VERSION 5.8 ;
BUSBITCHARS "[]" ;
DIVIDERCHAR "/" ;

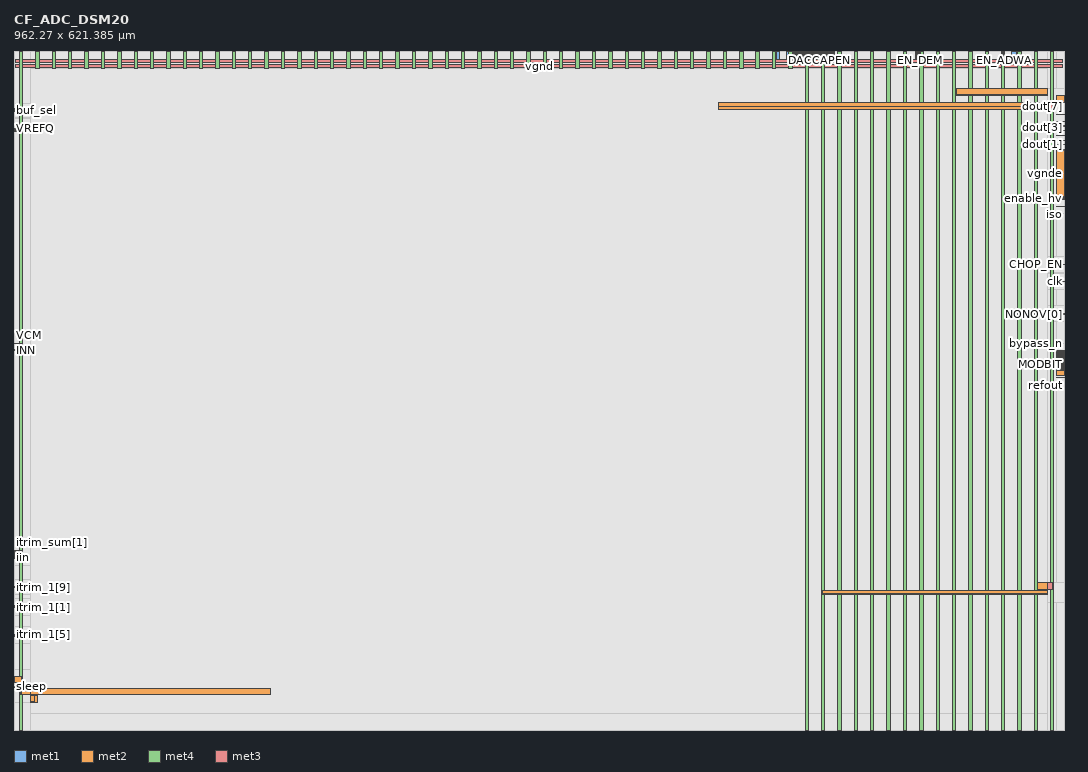
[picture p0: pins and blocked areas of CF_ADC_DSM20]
MACRO CF_ADC_DSM20
  CLASS BLOCK ;
  ORIGIN 0 0 ;
  FOREIGN CF_ADC_DSM20 0 0 ;
  SIZE 962.27 BY 621.385 ;
  PIN bw[0]
    DIRECTION INPUT ;
    USE SIGNAL ;
    PORT
      LAYER met1 ;
        RECT 713.61 614.485 713.81 621.385 ;
    END
  END bw[0]
  PIN bw[1]
    DIRECTION INPUT ;
    USE SIGNAL ;
    PORT
      LAYER met1 ;
        RECT 714.04 614.485 714.24 621.385 ;
    END
  END bw[1]
  PIN bw[2]
    DIRECTION INPUT ;
    USE SIGNAL ;
    PORT
      LAYER met1 ;
        RECT 714.47 614.485 714.67 621.385 ;
    END
  END bw[2]
  PIN SUMCAPIN[4]
    DIRECTION INPUT ;
    USE SIGNAL ;
    PORT
      LAYER met1 ;
        RECT 715.33 614.485 715.53 621.385 ;
    END
  END SUMCAPIN[4]
  PIN SUMCAPIN[3]
    DIRECTION INPUT ;
    USE SIGNAL ;
    PORT
      LAYER met1 ;
        RECT 715.76 614.485 715.96 621.385 ;
    END
  END SUMCAPIN[3]
  PIN SUMCAPIN[2]
    DIRECTION INPUT ;
    USE SIGNAL ;
    PORT
      LAYER met1 ;
        RECT 716.19 614.485 716.39 621.385 ;
    END
  END SUMCAPIN[2]
  PIN SUMCAPIN[1]
    DIRECTION INPUT ;
    USE SIGNAL ;
    PORT
      LAYER met1 ;
        RECT 716.62 614.485 716.82 621.385 ;
    END
  END SUMCAPIN[1]
  PIN SUMCAPIN[0]
    DIRECTION INPUT ;
    USE SIGNAL ;
    PORT
      LAYER met1 ;
        RECT 717.05 614.485 717.25 621.385 ;
    END
  END SUMCAPIN[0]
  PIN SUMCAPFB_EN
    DIRECTION INPUT ;
    USE SIGNAL ;
    PORT
      LAYER met1 ;
        RECT 717.48 614.485 717.68 621.385 ;
    END
  END SUMCAPFB_EN
  PIN SUMCAPFB[1]
    DIRECTION INPUT ;
    USE SIGNAL ;
    PORT
      LAYER met1 ;
        RECT 717.91 614.485 718.11 621.385 ;
    END
  END SUMCAPFB[1]
  PIN SUMCAPFB[2]
    DIRECTION INPUT ;
    USE SIGNAL ;
    PORT
      LAYER met1 ;
        RECT 718.34 614.485 718.54 621.385 ;
    END
  END SUMCAPFB[2]
  PIN SUMCAPFB[3]
    DIRECTION INPUT ;
    USE SIGNAL ;
    PORT
      LAYER met1 ;
        RECT 718.77 614.485 718.97 621.385 ;
    END
  END SUMCAPFB[3]
  PIN SUMCAPFB[0]
    DIRECTION INPUT ;
    USE SIGNAL ;
    PORT
      LAYER met1 ;
        RECT 719.2 614.485 719.4 621.385 ;
    END
  END SUMCAPFB[0]
  PIN refsel[15]
    DIRECTION INPUT ;
    USE SIGNAL ;
    PORT
      LAYER met1 ;
        RECT 719.63 614.485 719.83 621.385 ;
    END
  END refsel[15]
  PIN refsel[14]
    DIRECTION INPUT ;
    USE SIGNAL ;
    PORT
      LAYER met1 ;
        RECT 720.06 614.485 720.26 621.385 ;
    END
  END refsel[14]
  PIN refsel[13]
    DIRECTION INPUT ;
    USE SIGNAL ;
    PORT
      LAYER met1 ;
        RECT 720.49 614.485 720.69 621.385 ;
    END
  END refsel[13]
  PIN refsel[12]
    DIRECTION INPUT ;
    USE SIGNAL ;
    PORT
      LAYER met1 ;
        RECT 720.92 614.485 721.12 621.385 ;
    END
  END refsel[12]
  PIN refsel[11]
    DIRECTION INPUT ;
    USE SIGNAL ;
    PORT
      LAYER met1 ;
        RECT 721.35 614.485 721.55 621.385 ;
    END
  END refsel[11]
  PIN refsel[10]
    DIRECTION INPUT ;
    USE SIGNAL ;
    PORT
      LAYER met1 ;
        RECT 721.78 614.485 721.98 621.385 ;
    END
  END refsel[10]
  PIN refsel[9]
    DIRECTION INPUT ;
    USE SIGNAL ;
    PORT
      LAYER met1 ;
        RECT 722.21 614.485 722.41 621.385 ;
    END
  END refsel[9]
  PIN refsel[8]
    DIRECTION INPUT ;
    USE SIGNAL ;
    PORT
      LAYER met1 ;
        RECT 722.64 614.485 722.84 621.385 ;
    END
  END refsel[8]
  PIN refsel[7]
    DIRECTION INPUT ;
    USE SIGNAL ;
    PORT
      LAYER met1 ;
        RECT 723.07 614.485 723.27 621.385 ;
    END
  END refsel[7]
  PIN refsel[6]
    DIRECTION INPUT ;
    USE SIGNAL ;
    PORT
      LAYER met1 ;
        RECT 723.5 614.485 723.7 621.385 ;
    END
  END refsel[6]
  PIN refsel[5]
    DIRECTION INPUT ;
    USE SIGNAL ;
    PORT
      LAYER met1 ;
        RECT 723.93 614.485 724.13 621.385 ;
    END
  END refsel[5]
  PIN refsel[4]
    DIRECTION INPUT ;
    USE SIGNAL ;
    PORT
      LAYER met1 ;
        RECT 724.36 614.485 724.56 621.385 ;
    END
  END refsel[4]
  PIN refsel[3]
    DIRECTION INPUT ;
    USE SIGNAL ;
    PORT
      LAYER met1 ;
        RECT 724.79 614.485 724.99 621.385 ;
    END
  END refsel[3]
  PIN refsel[2]
    DIRECTION INPUT ;
    USE SIGNAL ;
    PORT
      LAYER met1 ;
        RECT 725.22 614.485 725.42 621.385 ;
    END
  END refsel[2]
  PIN refsel[1]
    DIRECTION INPUT ;
    USE SIGNAL ;
    PORT
      LAYER met1 ;
        RECT 725.65 614.485 725.85 621.385 ;
    END
  END refsel[1]
  PIN refsel[0]
    DIRECTION INPUT ;
    USE SIGNAL ;
    PORT
      LAYER met1 ;
        RECT 727.8 614.485 728 621.385 ;
    END
  END refsel[0]
  PIN SUMCAP3[0]
    DIRECTION INPUT ;
    USE SIGNAL ;
    PORT
      LAYER met1 ;
        RECT 726.08 614.485 726.28 621.385 ;
    END
  END SUMCAP3[0]
  PIN SUMCAP3[1]
    DIRECTION INPUT ;
    USE SIGNAL ;
    PORT
      LAYER met1 ;
        RECT 726.51 614.485 726.71 621.385 ;
    END
  END SUMCAP3[1]
  PIN SUMCAP3[2]
    DIRECTION INPUT ;
    USE SIGNAL ;
    PORT
      LAYER met1 ;
        RECT 726.94 614.485 727.14 621.385 ;
    END
  END SUMCAP3[2]
  PIN SUMCAP3_EN
    DIRECTION INPUT ;
    USE SIGNAL ;
    PORT
      LAYER met1 ;
        RECT 727.37 614.485 727.57 621.385 ;
    END
  END SUMCAP3_EN
  PIN SUMCAP2_EN
    DIRECTION INPUT ;
    USE SIGNAL ;
    PORT
      LAYER met1 ;
        RECT 728.23 614.485 728.43 621.385 ;
    END
  END SUMCAP2_EN
  PIN SUMCAP2[2]
    DIRECTION INPUT ;
    USE SIGNAL ;
    PORT
      LAYER met1 ;
        RECT 728.66 614.485 728.86 621.385 ;
    END
  END SUMCAP2[2]
  PIN SUMCAP2[1]
    DIRECTION INPUT ;
    USE SIGNAL ;
    PORT
      LAYER met1 ;
        RECT 729.09 614.485 729.29 621.385 ;
    END
  END SUMCAP2[1]
  PIN SUMCAP2[0]
    DIRECTION INPUT ;
    USE SIGNAL ;
    PORT
      LAYER met1 ;
        RECT 729.52 614.485 729.72 621.385 ;
    END
  END SUMCAP2[0]
  PIN SUMCAP1_EN
    DIRECTION INPUT ;
    USE SIGNAL ;
    PORT
      LAYER met1 ;
        RECT 729.95 614.485 730.15 621.385 ;
    END
  END SUMCAP1_EN
  PIN SUMCAP1[1]
    DIRECTION INPUT ;
    USE SIGNAL ;
    PORT
      LAYER met1 ;
        RECT 730.81 614.485 731.01 621.385 ;
    END
  END SUMCAP1[1]
  PIN SUMCAP1[0]
    DIRECTION INPUT ;
    USE SIGNAL ;
    PORT
      LAYER met1 ;
        RECT 731.24 614.485 731.44 621.385 ;
    END
  END SUMCAP1[0]
  PIN SUMCAP1[2]
    DIRECTION INPUT ;
    USE SIGNAL ;
    PORT
      LAYER met1 ;
        RECT 732.1 614.485 732.3 621.385 ;
    END
  END SUMCAP1[2]
  PIN IPCAP3[1]
    DIRECTION INPUT ;
    USE SIGNAL ;
    PORT
      LAYER met1 ;
        RECT 730.38 614.485 730.58 621.385 ;
    END
  END IPCAP3[1]
  PIN IPCAP3[2]
    DIRECTION INPUT ;
    USE SIGNAL ;
    PORT
      LAYER met1 ;
        RECT 731.67 614.485 731.87 621.385 ;
    END
  END IPCAP3[2]
  PIN IPCAP3[0]
    DIRECTION INPUT ;
    USE SIGNAL ;
    PORT
      LAYER met1 ;
        RECT 732.53 614.485 732.73 621.385 ;
    END
  END IPCAP3[0]
  PIN IPCAP2[2]
    DIRECTION INPUT ;
    USE SIGNAL ;
    PORT
      LAYER met1 ;
        RECT 732.96 614.485 733.16 621.385 ;
    END
  END IPCAP2[2]
  PIN IPCAP2[1]
    DIRECTION INPUT ;
    USE SIGNAL ;
    PORT
      LAYER met1 ;
        RECT 733.39 614.485 733.59 621.385 ;
    END
  END IPCAP2[1]
  PIN IPCAP2[0]
    DIRECTION INPUT ;
    USE SIGNAL ;
    PORT
      LAYER met1 ;
        RECT 733.82 614.485 734.02 621.385 ;
    END
  END IPCAP2[0]
  PIN FCAP3[3]
    DIRECTION INOUT ;
    USE SIGNAL ;
    PORT
      LAYER met1 ;
        RECT 734.25 614.485 734.45 621.385 ;
    END
  END FCAP3[3]
  PIN FCAP3[2]
    DIRECTION INOUT ;
    USE SIGNAL ;
    PORT
      LAYER met1 ;
        RECT 734.68 614.485 734.88 621.385 ;
    END
  END FCAP3[2]
  PIN FCAP3[0]
    DIRECTION INOUT ;
    USE SIGNAL ;
    PORT
      LAYER met1 ;
        RECT 735.54 614.485 735.74 621.385 ;
    END
  END FCAP3[0]
  PIN FCAP3[1]
    DIRECTION INOUT ;
    USE SIGNAL ;
    PORT
      LAYER met1 ;
        RECT 735.97 614.485 736.17 621.385 ;
    END
  END FCAP3[1]
  PIN FCAP2[3]
    DIRECTION INOUT ;
    USE SIGNAL ;
    PORT
      LAYER met1 ;
        RECT 735.11 614.485 735.31 621.385 ;
    END
  END FCAP2[3]
  PIN FCAP2[2]
    DIRECTION INOUT ;
    USE SIGNAL ;
    PORT
      LAYER met1 ;
        RECT 736.4 614.485 736.6 621.385 ;
    END
  END FCAP2[2]
  PIN FCAP2[1]
    DIRECTION INOUT ;
    USE SIGNAL ;
    PORT
      LAYER met1 ;
        RECT 736.83 614.485 737.03 621.385 ;
    END
  END FCAP2[1]
  PIN FCAP2[0]
    DIRECTION INOUT ;
    USE SIGNAL ;
    PORT
      LAYER met1 ;
        RECT 737.26 614.485 737.46 621.385 ;
    END
  END FCAP2[0]
  PIN DACCAPEN
    DIRECTION INPUT ;
    USE SIGNAL ;
    PORT
      LAYER met1 ;
        RECT 737.69 614.485 737.89 621.385 ;
    END
  END DACCAPEN
  PIN DACCAP[5]
    DIRECTION INPUT ;
    USE SIGNAL ;
    PORT
      LAYER met1 ;
        RECT 738.12 614.485 738.32 621.385 ;
    END
  END DACCAP[5]
  PIN DACCAP[4]
    DIRECTION INPUT ;
    USE SIGNAL ;
    PORT
      LAYER met1 ;
        RECT 738.55 614.485 738.75 621.385 ;
    END
  END DACCAP[4]
  PIN DACCAP[3]
    DIRECTION INPUT ;
    USE SIGNAL ;
    PORT
      LAYER met1 ;
        RECT 738.98 614.485 739.18 621.385 ;
    END
  END DACCAP[3]
  PIN DACCAP[0]
    DIRECTION INPUT ;
    USE SIGNAL ;
    PORT
      LAYER met1 ;
        RECT 739.41 614.485 739.61 621.385 ;
    END
  END DACCAP[0]
  PIN DACCAP[1]
    DIRECTION INPUT ;
    USE SIGNAL ;
    PORT
      LAYER met1 ;
        RECT 739.84 614.485 740.04 621.385 ;
    END
  END DACCAP[1]
  PIN DACCAP[2]
    DIRECTION INPUT ;
    USE SIGNAL ;
    PORT
      LAYER met1 ;
        RECT 740.27 614.485 740.47 621.385 ;
    END
  END DACCAP[2]
  PIN IPCAP1[6]
    DIRECTION INPUT ;
    USE SIGNAL ;
    PORT
      LAYER met1 ;
        RECT 740.7 614.485 740.9 621.385 ;
    END
  END IPCAP1[6]
  PIN IPCAP1[5]
    DIRECTION INPUT ;
    USE SIGNAL ;
    PORT
      LAYER met1 ;
        RECT 741.13 614.485 741.33 621.385 ;
    END
  END IPCAP1[5]
  PIN IPCAP1[4]
    DIRECTION INPUT ;
    USE SIGNAL ;
    PORT
      LAYER met1 ;
        RECT 741.56 614.485 741.76 621.385 ;
    END
  END IPCAP1[4]
  PIN IPCAP1[3]
    DIRECTION INPUT ;
    USE SIGNAL ;
    PORT
      LAYER met1 ;
        RECT 741.99 614.485 742.19 621.385 ;
    END
  END IPCAP1[3]
  PIN IPCAP1[2]
    DIRECTION INPUT ;
    USE SIGNAL ;
    PORT
      LAYER met1 ;
        RECT 742.42 614.485 742.62 621.385 ;
    END
  END IPCAP1[2]
  PIN IPCAP1[1]
    DIRECTION INPUT ;
    USE SIGNAL ;
    PORT
      LAYER met1 ;
        RECT 742.85 614.485 743.05 621.385 ;
    END
  END IPCAP1[1]
  PIN IPCAP1[0]
    DIRECTION INPUT ;
    USE SIGNAL ;
    PORT
      LAYER met1 ;
        RECT 745 614.485 745.2 621.385 ;
    END
  END IPCAP1[0]
  PIN FCAP1[3]
    DIRECTION INPUT ;
    USE SIGNAL ;
    PORT
      LAYER met1 ;
        RECT 743.28 614.485 743.48 621.385 ;
    END
  END FCAP1[3]
  PIN FCAP1[4]
    DIRECTION INPUT ;
    USE SIGNAL ;
    PORT
      LAYER met1 ;
        RECT 743.71 614.485 743.91 621.385 ;
    END
  END FCAP1[4]
  PIN FCAP1[5]
    DIRECTION INPUT ;
    USE SIGNAL ;
    PORT
      LAYER met1 ;
        RECT 744.14 614.485 744.34 621.385 ;
    END
  END FCAP1[5]
  PIN FCAP1[6]
    DIRECTION INPUT ;
    USE SIGNAL ;
    PORT
      LAYER met1 ;
        RECT 744.57 614.485 744.77 621.385 ;
    END
  END FCAP1[6]
  PIN FCAP1[2]
    DIRECTION INPUT ;
    USE SIGNAL ;
    PORT
      LAYER met1 ;
        RECT 745.43 614.485 745.63 621.385 ;
    END
  END FCAP1[2]
  PIN FCAP1[1]
    DIRECTION INPUT ;
    USE SIGNAL ;
    PORT
      LAYER met1 ;
        RECT 745.86 614.485 746.06 621.385 ;
    END
  END FCAP1[1]
  PIN FCAP1[0]
    DIRECTION INPUT ;
    USE SIGNAL ;
    PORT
      LAYER met1 ;
        RECT 746.29 614.485 746.49 621.385 ;
    END
  END FCAP1[0]
  PIN RESCAPEN
    DIRECTION INPUT ;
    USE SIGNAL ;
    PORT
      LAYER met1 ;
        RECT 746.72 614.485 746.92 621.385 ;
    END
  END RESCAPEN
  PIN FCHOP[1]
    DIRECTION INPUT ;
    USE SIGNAL ;
    PORT
      LAYER met2 ;
        RECT 955.37 339.81 962.27 340.01 ;
    END
  END FCHOP[1]
  PIN FCHOP[0]
    DIRECTION INPUT ;
    USE SIGNAL ;
    PORT
      LAYER met2 ;
        RECT 955.37 340.24 962.27 340.44 ;
    END
  END FCHOP[0]
  PIN ODET
    DIRECTION INPUT ;
    USE SIGNAL ;
    PORT
      LAYER met2 ;
        RECT 955.37 340.67 962.27 340.87 ;
    END
  END ODET
  PIN ODET_TH[4]
    DIRECTION INPUT ;
    USE SIGNAL ;
    PORT
      LAYER met2 ;
        RECT 955.37 341.1 962.27 341.3 ;
    END
  END ODET_TH[4]
  PIN ODET_TH[3]
    DIRECTION INPUT ;
    USE SIGNAL ;
    PORT
      LAYER met2 ;
        RECT 955.37 341.53 962.27 341.73 ;
    END
  END ODET_TH[3]
  PIN ODET_TH[2]
    DIRECTION INPUT ;
    USE SIGNAL ;
    PORT
      LAYER met2 ;
        RECT 955.37 341.96 962.27 342.16 ;
    END
  END ODET_TH[2]
  PIN ODET_TH[1]
    DIRECTION INPUT ;
    USE SIGNAL ;
    PORT
      LAYER met2 ;
        RECT 955.37 342.39 962.27 342.59 ;
    END
  END ODET_TH[1]
  PIN ODET_TH[0]
    DIRECTION INPUT ;
    USE SIGNAL ;
    PORT
      LAYER met2 ;
        RECT 955.37 342.82 962.27 343.02 ;
    END
  END ODET_TH[0]
  PIN RESET1
    DIRECTION INPUT ;
    USE SIGNAL ;
    PORT
      LAYER met2 ;
        RECT 955.37 343.25 962.27 343.45 ;
    END
  END RESET1
  PIN RESET2
    DIRECTION INPUT ;
    USE SIGNAL ;
    PORT
      LAYER met2 ;
        RECT 955.37 343.68 962.27 343.88 ;
    END
  END RESET2
  PIN RESET3
    DIRECTION INPUT ;
    USE SIGNAL ;
    PORT
      LAYER met2 ;
        RECT 955.37 344.11 962.27 344.31 ;
    END
  END RESET3
  PIN disable_mod
    DIRECTION INPUT ;
    USE SIGNAL ;
    PORT
      LAYER met2 ;
        RECT 955.37 344.54 962.27 344.74 ;
    END
  END disable_mod
  PIN dig_test_sel[2]
    DIRECTION INOUT ;
    USE SIGNAL ;
    PORT
      LAYER met2 ;
        RECT 955.37 344.97 962.27 345.17 ;
    END
  END dig_test_sel[2]
  PIN dig_test_sel[1]
    DIRECTION INOUT ;
    USE SIGNAL ;
    PORT
      LAYER met2 ;
        RECT 955.37 345.4 962.27 345.6 ;
    END
  END dig_test_sel[1]
  PIN dig_test_sel[0]
    DIRECTION INOUT ;
    USE SIGNAL ;
    PORT
      LAYER met2 ;
        RECT 955.37 345.94 962.27 346.08 ;
        RECT 955.37 345.83 962.27 345.99 ;
    END
  END dig_test_sel[0]
  PIN qlev[0]
    DIRECTION INPUT ;
    USE SIGNAL ;
    PORT
      LAYER met2 ;
        RECT 955.37 346.69 962.27 346.89 ;
    END
  END qlev[0]
  PIN qlev[1]
    DIRECTION INPUT ;
    USE SIGNAL ;
    PORT
      LAYER met2 ;
        RECT 955.37 346.26 962.27 346.46 ;
    END
  END qlev[1]
  PIN CHOP_EN
    DIRECTION INPUT ;
    USE SIGNAL ;
    PORT
      LAYER met2 ;
        RECT 955.37 426.54 962.27 426.86 ;
    END
  END CHOP_EN
  PIN clk
    DIRECTION INPUT ;
    USE SIGNAL ;
    PORT
      LAYER met2 ;
        RECT 955.37 410.95 962.27 411.21 ;
    END
  END clk
  PIN NONOV[1]
    DIRECTION INPUT ;
    USE SIGNAL ;
    PORT
      LAYER met2 ;
        RECT 955.37 381.45 962.27 381.71 ;
    END
  END NONOV[1]
  PIN NONOV[0]
    DIRECTION INPUT ;
    USE SIGNAL ;
    PORT
      LAYER met2 ;
        RECT 955.37 380.87 962.27 381.13 ;
    END
  END NONOV[0]
  PIN MODBIT
    DIRECTION INPUT ;
    USE SIGNAL ;
    PORT
      LAYER met2 ;
        RECT 955.37 334.785 962.27 334.925 ;
    END
  END MODBIT
  PIN SIGN
    DIRECTION INPUT ;
    USE SIGNAL ;
    PORT
      LAYER met2 ;
        RECT 955.37 334.355 962.27 334.555 ;
    END
  END SIGN
  PIN overload_det_one
    DIRECTION OUTPUT ;
    USE SIGNAL ;
    PORT
      LAYER met2 ;
        RECT 955.37 333.42 962.27 333.62 ;
    END
  END overload_det_one
  PIN overload_det_zero
    DIRECTION OUTPUT ;
    USE SIGNAL ;
    PORT
      LAYER met2 ;
        RECT 955.37 332.925 962.27 333.125 ;
    END
  END overload_det_zero
  PIN SCANOUTPUT
    DIRECTION OUTPUT ;
    USE SIGNAL ;
    PORT
      LAYER met2 ;
        RECT 955.37 332.465 962.27 332.665 ;
    END
  END SCANOUTPUT
  PIN buf_chopclk
    DIRECTION OUTPUT ;
    USE SIGNAL ;
    PORT
      LAYER met2 ;
        RECT 955.37 331.98 962.27 332.18 ;
    END
  END buf_chopclk
  PIN test_dig_out
    DIRECTION OUTPUT ;
    USE SIGNAL ;
    PORT
      LAYER met2 ;
        RECT 955.37 331.485 962.27 331.685 ;
    END
  END test_dig_out
  PIN SUMP_TEST
    DIRECTION OUTPUT ;
    USE SIGNAL ;
    PORT
      LAYER met2 ;
        RECT 955.37 330.95 962.27 331.15 ;
    END
  END SUMP_TEST
  PIN dout[7]
    DIRECTION INOUT ;
    USE SIGNAL ;
    PORT
      LAYER met2 ;
        RECT 955.37 563.62 962.27 563.82 ;
    END
  END dout[7]
  PIN bw[3]
    DIRECTION INPUT ;
    USE SIGNAL ;
    PORT
      LAYER met1 ;
        RECT 713.18 614.485 713.38 621.385 ;
    END
  END bw[3]
  PIN dout[6]
    DIRECTION INOUT ;
    USE SIGNAL ;
    PORT
      LAYER met2 ;
        RECT 955.37 557.5 962.27 557.7 ;
    END
  END dout[6]
  PIN dout[5]
    DIRECTION INOUT ;
    USE SIGNAL ;
    PORT
      LAYER met2 ;
        RECT 955.37 553.51 962.27 553.71 ;
    END
  END dout[5]
  PIN dout[4]
    DIRECTION INOUT ;
    USE SIGNAL ;
    PORT
      LAYER met2 ;
        RECT 955.37 549.26 962.27 549.46 ;
    END
  END dout[4]
  PIN dout[3]
    DIRECTION INOUT ;
    USE SIGNAL ;
    PORT
      LAYER met2 ;
        RECT 955.37 544.81 962.27 545.01 ;
    END
  END dout[3]
  PIN dout[2]
    DIRECTION INOUT ;
    USE SIGNAL ;
    PORT
      LAYER met2 ;
        RECT 955.37 540.425 962.27 540.625 ;
    END
  END dout[2]
  PIN dout[1]
    DIRECTION INOUT ;
    USE SIGNAL ;
    PORT
      LAYER met2 ;
        RECT 955.37 536.19 962.27 536.39 ;
    END
  END dout[1]
  PIN dout[0]
    DIRECTION INOUT ;
    USE SIGNAL ;
    PORT
      LAYER met2 ;
        RECT 955.37 531.89 962.27 532.09 ;
    END
  END dout[0]
  PIN refout
    DIRECTION OUTPUT ;
    USE SIGNAL ;
    PORT
      LAYER met2 ;
        RECT 955.37 323.2 962.27 323.4 ;
    END
  END refout
  PIN vpwr
    DIRECTION INPUT ;
    USE POWER ;
    PORT
      LAYER met2 ;
        RECT 14.99 32.43 234.73 38.4 ;
        RECT 6.31 32.43 234.73 38.4 ;
        RECT 863.905 582.355 947.27 588.115 ;
        RECT 863.905 581.575 947.27 588.115 ;
        RECT 741.135 124.835 947.28 127.835 ;
        RECT 741.135 124.055 947.28 127.835 ;
      LAYER met4 ;
        RECT 5 0 8.1 621.385 ;
        RECT 35 606.53 38.1 621.385 ;
        RECT 65 606.53 68.1 621.385 ;
        RECT 95 606.53 98.1 621.385 ;
        RECT 125 606.53 128.1 621.385 ;
        RECT 155 606.53 158.1 621.385 ;
        RECT 185 606.53 188.1 621.385 ;
        RECT 215 606.53 218.1 621.385 ;
        RECT 245 606.53 248.1 621.385 ;
        RECT 275 606.53 278.1 621.385 ;
        RECT 305 606.53 308.1 621.385 ;
        RECT 335 606.53 338.1 621.385 ;
        RECT 365 606.53 368.1 621.385 ;
        RECT 395 606.53 398.1 621.385 ;
        RECT 425 606.53 428.1 621.385 ;
        RECT 455 606.53 458.1 621.385 ;
        RECT 485 606.53 488.1 621.385 ;
        RECT 515 606.53 518.1 621.385 ;
        RECT 545 606.53 548.1 621.385 ;
        RECT 575 606.53 578.1 621.385 ;
        RECT 605 606.53 608.1 621.385 ;
        RECT 635 606.53 638.1 621.385 ;
        RECT 665 606.53 668.1 621.385 ;
        RECT 695 606.53 698.1 621.385 ;
        RECT 725 0 728.1 621.385 ;
        RECT 755 0 758.1 621.385 ;
        RECT 785 0 788.1 621.385 ;
        RECT 815 0 818.1 621.385 ;
        RECT 845 0 848.1 621.385 ;
        RECT 875 0 878.1 621.385 ;
        RECT 905 0 908.1 621.385 ;
        RECT 935 0 938.1 621.385 ;
      LAYER met3 ;
        RECT 6.31 32.43 6.79 38.4 ;
        RECT 863.905 581.575 947.27 582.055 ;
        RECT 741.135 124.055 947.28 124.535 ;
        RECT 1.23 611.685 961.04 614.785 ;
    END
  END vpwr
  PIN vgnd
    DIRECTION INPUT ;
    USE GROUND ;
    PORT
      LAYER met2 ;
        RECT 15 26.485 19 31.39 ;
        RECT 15 25.42 19 26.485 ;
        RECT 15 25.42 21.79 31.39 ;
        RECT 942.27 571.53 947.285 574.675 ;
        RECT 645.36 568.675 947.285 571.53 ;
        RECT 645.36 568.675 947.285 574.675 ;
        RECT 938.365 128.99 947.27 134.995 ;
        RECT 938.365 128.99 947.27 134.995 ;
      LAYER met4 ;
        RECT 20 606.53 23.1 621.385 ;
        RECT 50 606.53 53.1 621.385 ;
        RECT 80 606.53 83.1 621.385 ;
        RECT 110 606.53 113.1 621.385 ;
        RECT 140 606.53 143.1 621.385 ;
        RECT 170 606.53 173.1 621.385 ;
        RECT 200 606.53 203.1 621.385 ;
        RECT 230 606.53 233.1 621.385 ;
        RECT 260 606.53 263.1 621.385 ;
        RECT 290 606.53 293.1 621.385 ;
        RECT 320 606.53 323.1 621.385 ;
        RECT 350 606.53 353.1 621.385 ;
        RECT 380 606.53 383.1 621.385 ;
        RECT 410 606.53 413.1 621.385 ;
        RECT 440 606.53 443.1 621.385 ;
        RECT 470 606.53 473.1 621.385 ;
        RECT 500 606.53 503.1 621.385 ;
        RECT 530 606.53 533.1 621.385 ;
        RECT 560 606.53 563.1 621.385 ;
        RECT 590 606.53 593.1 621.385 ;
        RECT 620 606.53 623.1 621.385 ;
        RECT 650 606.53 653.1 621.385 ;
        RECT 680 606.53 683.1 621.385 ;
        RECT 710 606.53 713.1 621.385 ;
        RECT 740 0 743.1 621.385 ;
        RECT 770 0 773.1 621.385 ;
        RECT 800 0 803.1 621.385 ;
        RECT 830 0 833.1 621.385 ;
        RECT 860 0 863.1 621.385 ;
        RECT 890 0 893.1 621.385 ;
        RECT 920 0 923.1 621.385 ;
        RECT 950 0 953.1 621.385 ;
      LAYER met3 ;
        RECT 21.31 25.42 21.79 31.39 ;
        RECT 645.36 568.675 951.79 574.675 ;
        RECT 938.365 128.99 951.79 134.995 ;
        RECT 1.23 606.885 961.04 609.985 ;
    END
  END vgnd
  PIN RESCAP[2]
    DIRECTION INPUT ;
    USE SIGNAL ;
    PORT
      LAYER met1 ;
        RECT 747.15 614.485 747.35 621.385 ;
    END
  END RESCAP[2]
  PIN RESCAP[0]
    DIRECTION INPUT ;
    USE SIGNAL ;
    PORT
      LAYER met1 ;
        RECT 748.01 614.485 748.21 621.385 ;
    END
  END RESCAP[0]
  PIN RESCAP[1]
    DIRECTION INPUT ;
    USE SIGNAL ;
    PORT
      LAYER met1 ;
        RECT 749.3 614.485 749.5 621.385 ;
    END
  END RESCAP[1]
  PIN IPCAP1OFFSET
    DIRECTION INPUT ;
    USE SIGNAL ;
    PORT
      LAYER met1 ;
        RECT 747.58 614.485 747.78 621.385 ;
    END
  END IPCAP1OFFSET
  PIN IPCAP3EN
    DIRECTION INPUT ;
    USE SIGNAL ;
    PORT
      LAYER met1 ;
        RECT 748.44 614.485 748.64 621.385 ;
    END
  END IPCAP3EN
  PIN IPCAP2EN
    DIRECTION INPUT ;
    USE SIGNAL ;
    PORT
      LAYER met1 ;
        RECT 748.87 614.485 749.07 621.385 ;
    END
  END IPCAP2EN
  PIN IPCAP1EN
    DIRECTION INPUT ;
    USE SIGNAL ;
    PORT
      LAYER met1 ;
        RECT 749.73 614.485 749.93 621.385 ;
    END
  END IPCAP1EN
  PIN FCAP3EN
    DIRECTION INPUT ;
    USE SIGNAL ;
    PORT
      LAYER met1 ;
        RECT 750.16 614.485 750.36 621.385 ;
    END
  END FCAP3EN
  PIN FCAP2EN
    DIRECTION INPUT ;
    USE SIGNAL ;
    PORT
      LAYER met1 ;
        RECT 750.59 614.485 750.79 621.385 ;
    END
  END FCAP2EN
  PIN FCAP1EN
    DIRECTION INPUT ;
    USE SIGNAL ;
    PORT
      LAYER met1 ;
        RECT 751.45 614.485 751.65 621.385 ;
    END
  END FCAP1EN
  PIN FCAP1OFFSET
    DIRECTION INPUT ;
    USE SIGNAL ;
    PORT
      LAYER met1 ;
        RECT 751.02 614.485 751.22 621.385 ;
    END
  END FCAP1OFFSET
  PIN SUMCAPIN_EN
    DIRECTION INPUT ;
    USE SIGNAL ;
    PORT
      LAYER met1 ;
        RECT 714.9 614.485 715.1 621.385 ;
    END
  END SUMCAPIN_EN
  PIN INP
    DIRECTION INPUT ;
    USE SIGNAL ;
    PORT
      LAYER met1 ;
        RECT 0 348.745 6.9 349.045 ;
    END
  END INP
  PIN INN
    DIRECTION INPUT ;
    USE SIGNAL ;
    PORT
      LAYER met1 ;
        RECT 0 347.785 6.9 348.085 ;
    END
  END INN
  PIN EN_DEM
    DIRECTION INPUT ;
    USE SIGNAL ;
    PORT
      LAYER met1 ;
        RECT 830.565 614.485 830.765 621.385 ;
    END
  END EN_DEM
  PIN test[7]
    DIRECTION INOUT ;
    USE SIGNAL ;
    PORT
      LAYER met1 ;
        RECT 830.085 614.485 830.285 621.385 ;
    END
  END test[7]
  PIN test[6]
    DIRECTION INOUT ;
    USE SIGNAL ;
    PORT
      LAYER met1 ;
        RECT 829.605 614.485 829.805 621.385 ;
    END
  END test[6]
  PIN test[5]
    DIRECTION INOUT ;
    USE SIGNAL ;
    PORT
      LAYER met1 ;
        RECT 829.125 614.485 829.325 621.385 ;
    END
  END test[5]
  PIN test[4]
    DIRECTION INOUT ;
    USE SIGNAL ;
    PORT
      LAYER met1 ;
        RECT 828.645 614.485 828.845 621.385 ;
    END
  END test[4]
  PIN test[3]
    DIRECTION INOUT ;
    USE SIGNAL ;
    PORT
      LAYER met1 ;
        RECT 828.165 614.485 828.365 621.385 ;
    END
  END test[3]
  PIN test[2]
    DIRECTION INOUT ;
    USE SIGNAL ;
    PORT
      LAYER met1 ;
        RECT 827.685 614.485 827.885 621.385 ;
    END
  END test[2]
  PIN test[1]
    DIRECTION INOUT ;
    USE SIGNAL ;
    PORT
      LAYER met1 ;
        RECT 827.205 614.485 827.405 621.385 ;
    END
  END test[1]
  PIN test[0]
    DIRECTION INOUT ;
    USE SIGNAL ;
    PORT
      LAYER met1 ;
        RECT 826.725 614.485 826.925 621.385 ;
    END
  END test[0]
  PIN TESTMODE
    DIRECTION INPUT ;
    USE SIGNAL ;
    PORT
      LAYER met1 ;
        RECT 826.245 614.485 826.445 621.385 ;
    END
  END TESTMODE
  PIN EN_DWA
    DIRECTION INPUT ;
    USE SIGNAL ;
    PORT
      LAYER met1 ;
        RECT 906.96 614.485 907.16 621.385 ;
    END
  END EN_DWA
  PIN SCANINPUT
    DIRECTION INPUT ;
    USE SIGNAL ;
    PORT
      LAYER met1 ;
        RECT 906 614.485 906.2 621.385 ;
    END
  END SCANINPUT
  PIN SCANMODE
    DIRECTION INPUT ;
    USE SIGNAL ;
    PORT
      LAYER met1 ;
        RECT 905.04 614.485 905.24 621.385 ;
    END
  END SCANMODE
  PIN SCANCLK
    DIRECTION INPUT ;
    USE SIGNAL ;
    PORT
      LAYER met1 ;
        RECT 905.52 614.485 905.72 621.385 ;
    END
  END SCANCLK
  PIN SCANEN
    DIRECTION INPUT ;
    USE SIGNAL ;
    PORT
      LAYER met1 ;
        RECT 906.48 614.485 906.68 621.385 ;
    END
  END SCANEN
  PIN reset_b
    DIRECTION INPUT ;
    USE SIGNAL ;
    PORT
      LAYER met1 ;
        RECT 904.56 614.485 904.76 621.385 ;
    END
  END reset_b
  PIN VCM
    DIRECTION INPUT ;
    USE SIGNAL ;
    PORT
      LAYER met1 ;
        RECT 0 354.06 6.9 354.36 ;
    END
  END VCM
  PIN vgndd_vnb
    DIRECTION INOUT ;
    USE SIGNAL ;
    PORT
      LAYER met1 ;
        RECT 913.8 614.485 918.775 621.385 ;
    END
  END vgndd_vnb
  PIN VGND_DAC
    DIRECTION INPUT ;
    USE SIGNAL ;
    PORT
      LAYER met1 ;
        RECT 0 548.45 6.9 549.225 ;
    END
  END VGND_DAC
  PIN VREFQ
    DIRECTION INPUT ;
    USE SIGNAL ;
    PORT
      LAYER met1 ;
        RECT 0 550.8 6.9 551.04 ;
    END
  END VREFQ
  PIN EN_ADWA
    DIRECTION INPUT ;
    USE SIGNAL ;
    PORT
      LAYER met1 ;
        RECT 907.48 614.485 907.68 621.385 ;
    END
  END EN_ADWA
  PIN PBUF_INP
    DIRECTION INPUT ;
    USE SIGNAL ;
    PORT
      LAYER met1 ;
        RECT 0 568.455 6.9 568.705 ;
    END
  END PBUF_INP
  PIN VREF
    DIRECTION INPUT ;
    USE SIGNAL ;
    PORT
      LAYER met1 ;
        RECT 0 549.88 6.9 550.185 ;
    END
  END VREF
  PIN PBUF_INN
    DIRECTION INPUT ;
    USE SIGNAL ;
    PORT
      LAYER met1 ;
        RECT 0 569.215 6.9 569.465 ;
    END
  END PBUF_INN
  PIN vgnde_vnb
    DIRECTION INPUT ;
    USE SIGNAL ;
    PORT
      LAYER met2 ;
        RECT 955.37 487.325 962.27 487.72 ;
    END
  END vgnde_vnb
  PIN vgnde
    DIRECTION INPUT ;
    USE SIGNAL ;
    PORT
      LAYER met2 ;
        RECT 955.37 488.97 962.27 531.195 ;
        RECT 955.37 487.965 962.27 488.97 ;
    END
  END vgnde
  PIN vpwr_ext
    DIRECTION INPUT ;
    USE SIGNAL ;
    PORT
      LAYER met1 ;
        RECT 698.665 614.485 701.655 621.385 ;
    END
  END vpwr_ext
  PIN vpwr_cp
    DIRECTION INPUT ;
    USE SIGNAL ;
    PORT
      LAYER met2 ;
        RECT 955.37 324.72 962.27 329.135 ;
    END
  END vpwr_cp
  PIN vpwr_cp_dc
    DIRECTION INOUT ;
    USE SIGNAL ;
    PORT
      LAYER met1 ;
        RECT 707.82 614.485 709.49 621.385 ;
    END
  END vpwr_cp_dc
  PIN SUMN_TEST
    DIRECTION OUTPUT ;
    USE SIGNAL ;
    PORT
      LAYER met2 ;
        RECT 955.37 330.455 962.27 330.655 ;
    END
  END SUMN_TEST
  PIN bypass_n
    DIRECTION INPUT ;
    USE SIGNAL ;
    PORT
      LAYER met2 ;
        RECT 955.37 347.12 962.27 347.26 ;
    END
  END bypass_n
  PIN bypass_p
    DIRECTION INPUT ;
    USE SIGNAL ;
    PORT
      LAYER met2 ;
        RECT 955.37 347.49 962.27 347.63 ;
    END
  END bypass_p
  PIN phi2_buffer
    DIRECTION INOUT ;
    USE SIGNAL ;
    PORT
      LAYER met2 ;
        RECT 955.37 335.2 962.27 335.34 ;
    END
  END phi2_buffer
  PIN iso
    DIRECTION INOUT ;
    USE SIGNAL ;
    PORT
      LAYER met2 ;
        RECT 955.37 479.9 962.27 480.04 ;
    END
  END iso
  PIN enable_hv
    DIRECTION INOUT ;
    USE SIGNAL ;
    PORT
      LAYER met2 ;
        RECT 955.37 486.565 962.27 486.705 ;
    END
  END enable_hv
  PIN MODINPUT
    DIRECTION INPUT ;
    USE SIGNAL ;
    PORT
      LAYER met2 ;
        RECT 955.37 333.89 962.27 334.09 ;
    END
  END MODINPUT
  PIN sleep
    DIRECTION INOUT ;
    USE SIGNAL ;
    PORT
      LAYER met2 ;
        RECT 0 39.295 6.9 39.535 ;
    END
  END sleep
  PIN buf_sel
    DIRECTION INPUT ;
    USE SIGNAL ;
    PORT
      LAYER met2 ;
        RECT 0 567.235 6.9 567.475 ;
    END
  END buf_sel
  PIN vpwrd_int
    DIRECTION INOUT ;
    USE SIGNAL ;
    PORT
      LAYER met2 ;
        RECT 955.37 575.185 962.27 581.185 ;
    END
  END vpwrd_int
  PIN vpwr_int
    DIRECTION INOUT ;
    USE SIGNAL ;
    PORT
      LAYER met2 ;
        RECT 0 43.95 6.9 48.75 ;
    END
  END vpwr_int
  PIN iinc
    DIRECTION INPUT ;
    USE SIGNAL ;
    PORT
      LAYER met2 ;
        RECT 0 158.35 6.9 158.65 ;
    END
  END iinc
  PIN itrim_1[9]
    DIRECTION INPUT ;
    USE SIGNAL ;
    PORT
      LAYER met2 ;
        RECT 0 130.785 6.9 131.095 ;
    END
  END itrim_1[9]
  PIN itrim_1[1]
    DIRECTION INPUT ;
    USE SIGNAL ;
    PORT
      LAYER met2 ;
        RECT 0 112.165 6.9 112.525 ;
    END
  END itrim_1[1]
  PIN itrim_1[2]
    DIRECTION INPUT ;
    USE SIGNAL ;
    PORT
      LAYER met2 ;
        RECT 0 112.675 6.9 113.035 ;
    END
  END itrim_1[2]
  PIN itrim_1[3]
    DIRECTION INPUT ;
    USE SIGNAL ;
    PORT
      LAYER met2 ;
        RECT 0 113.185 6.9 113.545 ;
    END
  END itrim_1[3]
  PIN itrim_1[4]
    DIRECTION INPUT ;
    USE SIGNAL ;
    PORT
      LAYER met2 ;
        RECT 0 113.695 6.9 114.055 ;
    END
  END itrim_1[4]
  PIN itrim_1[8]
    DIRECTION INPUT ;
    USE SIGNAL ;
    PORT
      LAYER met2 ;
        RECT 0 85.83 6.9 86.19 ;
    END
  END itrim_1[8]
  PIN itrim_1[7]
    DIRECTION INPUT ;
    USE SIGNAL ;
    PORT
      LAYER met2 ;
        RECT 0 86.34 6.9 86.7 ;
    END
  END itrim_1[7]
  PIN itrim_1[6]
    DIRECTION INPUT ;
    USE SIGNAL ;
    PORT
      LAYER met2 ;
        RECT 0 86.85 6.9 87.21 ;
    END
  END itrim_1[6]
  PIN itrim_1[5]
    DIRECTION INPUT ;
    USE SIGNAL ;
    PORT
      LAYER met2 ;
        RECT 0 87.36 6.9 87.72 ;
    END
  END itrim_1[5]
  PIN iin
    DIRECTION INPUT ;
    USE SIGNAL ;
    PORT
      LAYER met2 ;
        RECT 0 157.87 6.9 158.17 ;
    END
  END iin
  PIN itrim_sum[0]
    DIRECTION INPUT ;
    USE SIGNAL ;
    PORT
      LAYER met2 ;
        RECT 0 164.595 6.9 164.895 ;
    END
  END itrim_sum[0]
  PIN itrim_sum[1]
    DIRECTION INPUT ;
    USE SIGNAL ;
    PORT
      LAYER met2 ;
        RECT 0 164.115 6.9 164.415 ;
    END
  END itrim_sum[1]
  PIN itrim_sum[2]
    DIRECTION INPUT ;
    USE SIGNAL ;
    PORT
      LAYER met2 ;
        RECT 0 163.635 6.9 163.935 ;
    END
  END itrim_sum[2]
  PIN itrim_sum[3]
    DIRECTION INPUT ;
    USE SIGNAL ;
    PORT
      LAYER met2 ;
        RECT 0 163.155 6.9 163.455 ;
    END
  END itrim_sum[3]
  PIN itrim_sum[4]
    DIRECTION INPUT ;
    USE SIGNAL ;
    PORT
      LAYER met2 ;
        RECT 0 162.675 6.9 162.975 ;
    END
  END itrim_sum[4]
  PIN itrim_2_3[0]
    DIRECTION INPUT ;
    USE SIGNAL ;
    PORT
      LAYER met2 ;
        RECT 0 161.715 6.9 162.015 ;
    END
  END itrim_2_3[0]
  PIN itrim_2_3[1]
    DIRECTION INPUT ;
    USE SIGNAL ;
    PORT
      LAYER met2 ;
        RECT 0 161.235 6.9 161.535 ;
    END
  END itrim_2_3[1]
  PIN itrim_2_3[2]
    DIRECTION INPUT ;
    USE SIGNAL ;
    PORT
      LAYER met2 ;
        RECT 0 160.755 6.9 161.055 ;
    END
  END itrim_2_3[2]
  PIN itrim_2_3[3]
    DIRECTION INPUT ;
    USE SIGNAL ;
    PORT
      LAYER met2 ;
        RECT 0 160.275 6.9 160.575 ;
    END
  END itrim_2_3[3]
  PIN itrim_2_3[4]
    DIRECTION INPUT ;
    USE SIGNAL ;
    PORT
      LAYER met2 ;
        RECT 0 159.795 6.9 160.095 ;
    END
  END itrim_2_3[4]
  PIN itrim_sum[5]
    DIRECTION INPUT ;
    USE SIGNAL ;
    PORT
      LAYER met2 ;
        RECT 0 162.195 6.9 162.495 ;
    END
  END itrim_sum[5]
  PIN itrim_2_3[5]
    DIRECTION INPUT ;
    USE SIGNAL ;
    PORT
      LAYER met2 ;
        RECT 0 159.315 6.9 159.615 ;
    END
  END itrim_2_3[5]
  PIN itrim_1[0]
    DIRECTION INPUT ;
    USE SIGNAL ;
    PORT
      LAYER met2 ;
        RECT 0 157.39 6.9 157.69 ;
    END
  END itrim_1[0]
  PIN itrim_comp[3]
    DIRECTION INPUT ;
    USE SIGNAL ;
    PORT
      LAYER met2 ;
        RECT 955.37 335.57 962.27 335.71 ;
    END
  END itrim_comp[3]
  PIN itrim_comp[2]
    DIRECTION INPUT ;
    USE SIGNAL ;
    PORT
      LAYER met2 ;
        RECT 955.37 335.94 962.27 336.14 ;
    END
  END itrim_comp[2]
  PIN itrim_comp[1]
    DIRECTION INPUT ;
    USE SIGNAL ;
    PORT
      LAYER met2 ;
        RECT 955.37 336.37 962.27 336.57 ;
    END
  END itrim_comp[1]
  PIN itrim_comp[0]
    DIRECTION INPUT ;
    USE SIGNAL ;
    PORT
      LAYER met2 ;
        RECT 955.37 336.8 962.27 337 ;
    END
  END itrim_comp[0]
  PIN BUF_CHOP_EN
    DIRECTION INPUT ;
    USE SIGNAL ;
    PORT
      LAYER met2 ;
        RECT 955.37 337.23 962.27 337.43 ;
    END
  END BUF_CHOP_EN
  PIN BUF_FCHOP[2]
    DIRECTION INPUT ;
    USE SIGNAL ;
    PORT
      LAYER met2 ;
        RECT 955.37 337.66 962.27 337.86 ;
    END
  END BUF_FCHOP[2]
  PIN BUF_FCHOP[1]
    DIRECTION INPUT ;
    USE SIGNAL ;
    PORT
      LAYER met2 ;
        RECT 955.37 338.09 962.27 338.29 ;
    END
  END BUF_FCHOP[1]
  PIN BUF_FCHOP[0]
    DIRECTION INPUT ;
    USE SIGNAL ;
    PORT
      LAYER met2 ;
        RECT 955.37 338.52 962.27 338.72 ;
    END
  END BUF_FCHOP[0]
  PIN RESET_DEC_INPUT
    DIRECTION INPUT ;
    USE SIGNAL ;
    PORT
      LAYER met2 ;
        RECT 955.37 338.95 962.27 339.15 ;
    END
  END RESET_DEC_INPUT
  PIN FCHOP[2]
    DIRECTION INPUT ;
    USE SIGNAL ;
    PORT
      LAYER met2 ;
        RECT 955.37 339.38 962.27 339.58 ;
    END
  END FCHOP[2]
  OBS
    LAYER li1 ;
      RECT 739.84 530.05 740.04 559.94 ;
      RECT 742.42 530.05 742.62 559.94 ;
      RECT 738.98 530.05 739.18 559.94 ;
      RECT 743.71 528.355 743.91 558.945 ;
      RECT 745 530.05 745.2 559.94 ;
      RECT 746.72 530.05 746.92 559.94 ;
      RECT 751.02 530.05 751.22 559.94 ;
      RECT 748.87 528.355 749.07 558.945 ;
      RECT 747.15 528.355 747.35 558.945 ;
      RECT 750.59 528.355 750.79 558.945 ;
      RECT 748.01 528.355 748.21 558.945 ;
      RECT 746.29 528.355 746.49 558.945 ;
      RECT 745.43 528.355 745.63 558.945 ;
      RECT 749.73 528.355 749.93 558.945 ;
      RECT 747.58 530.05 747.78 559.94 ;
      RECT 748.44 530.05 748.64 559.94 ;
      RECT 745.86 530.05 746.06 559.94 ;
      RECT 750.16 530.05 750.36 559.94 ;
      RECT 749.3 530.05 749.5 559.94 ;
      RECT 753.625 530.05 753.825 561.29 ;
      RECT 752.765 530.05 752.965 559.94 ;
      RECT 754.915 528.355 755.115 561.29 ;
      RECT 754.485 530.05 754.685 561.29 ;
      RECT 755.345 530.05 755.545 561.29 ;
      RECT 754.055 528.355 754.255 561.29 ;
      RECT 753.195 528.355 753.395 561.29 ;
      RECT 751.45 528.355 751.65 558.945 ;
      RECT 755.775 528.355 755.975 561.29 ;
      RECT 752.335 528.355 752.535 558.945 ;
      RECT 756.635 528.355 756.835 561.29 ;
      RECT 751.905 530.05 752.105 559.94 ;
      RECT 756.205 530.05 756.405 561.29 ;
      RECT 906.185 538.79 907.085 538.96 ;
      RECT 906.915 537.38 907.085 538.79 ;
      RECT 906.685 535.43 906.855 536.51 ;
      RECT 913.23 501.24 913.46 551.67 ;
      RECT 863.675 575.33 895.195 575.62 ;
      RECT 863.53 582.835 895.065 584.835 ;
      RECT 941.92 526.615 943.27 591.885 ;
      RECT 531.5 527.74 532.79 573.39 ;
      RECT 532.475 518.405 532.705 527.74 ;
      RECT 502.615 591.39 503.145 591.685 ;
      RECT 534.665 583.625 543.285 584.145 ;
      RECT 520.3 591.525 520.96 591.695 ;
      RECT 521.965 591.525 522.5 591.695 ;
      RECT 563.74 591.525 564.4 591.695 ;
      RECT 562.2 591.525 562.72 591.695 ;
      RECT 580.66 591.525 581.32 591.695 ;
      RECT 582.325 591.525 582.86 591.695 ;
      RECT 535.555 588.07 536.225 588.435 ;
      RECT 503.375 591.525 504.075 591.695 ;
      RECT 639.345 545.715 649.735 545.885 ;
      RECT 639.345 545.885 639.515 559.945 ;
      RECT 639.345 531.075 649.735 531.805 ;
      RECT 639.345 531.805 639.515 545.715 ;
      RECT 649.565 558.005 649.8 559.945 ;
      RECT 649.565 519.03 649.735 531.075 ;
      RECT 649.565 517.015 649.8 519.03 ;
      RECT 649.565 545.885 649.735 558.005 ;
      RECT 649.565 531.805 649.735 545.715 ;
      RECT 639.345 517.015 639.515 531.075 ;
      RECT 639.345 559.945 649.8 560.475 ;
      RECT 639.345 516.7 649.8 517.015 ;
      RECT 633.75 515.34 654.875 516.405 ;
      RECT 638.96 548.245 639.13 560.82 ;
      RECT 650 516.405 650.255 560.82 ;
      RECT 638.96 560.825 650.17 560.99 ;
      RECT 638.96 560.82 650.255 560.825 ;
      RECT 638.96 516.405 639.13 528.625 ;
      RECT 617.03 591.525 617.69 591.695 ;
      RECT 615.49 591.525 616.025 591.695 ;
      RECT 633.95 591.525 634.61 591.695 ;
      RECT 635.615 591.525 636.15 591.695 ;
      RECT 667.565 591.525 668.225 591.695 ;
      RECT 665.885 591.525 666.58 591.695 ;
      RECT 656.36 505.08 710.11 506.05 ;
      RECT 656.36 517.62 710.11 518.7 ;
      RECT 654.43 498.96 710.935 499.64 ;
      RECT 654.43 511.505 710.935 512.185 ;
      RECT 682.79 524.755 682.99 550.055 ;
      RECT 682.355 524.755 682.555 550.055 ;
      RECT 684.095 524.755 684.295 550.055 ;
      RECT 688.445 524.755 688.645 550.055 ;
      RECT 686.27 524.755 686.47 550.055 ;
      RECT 686.705 524.755 686.905 550.055 ;
      RECT 688.01 524.755 688.21 550.055 ;
      RECT 687.14 524.755 687.34 550.055 ;
      RECT 688.88 524.755 689.08 550.055 ;
      RECT 685.835 524.755 686.035 550.055 ;
      RECT 687.575 524.755 687.775 550.055 ;
      RECT 684.965 524.755 685.165 550.055 ;
      RECT 685.4 524.755 685.6 550.055 ;
      RECT 683.66 524.755 683.86 550.055 ;
      RECT 684.53 524.755 684.73 550.055 ;
      RECT 683.225 524.755 683.425 550.055 ;
      RECT 684.485 591.525 685.145 591.695 ;
      RECT 713.18 530.05 713.38 559.94 ;
      RECT 713.61 528.355 713.81 558.945 ;
      RECT 717.05 528.355 717.25 558.945 ;
      RECT 714.47 528.355 714.67 558.945 ;
      RECT 718.34 530.05 718.54 559.94 ;
      RECT 715.33 528.355 715.53 558.945 ;
      RECT 718.77 528.355 718.97 558.945 ;
      RECT 716.19 528.355 716.39 558.945 ;
      RECT 717.91 528.355 718.11 558.945 ;
      RECT 719.63 528.355 719.83 557.625 ;
      RECT 720.06 530.05 720.26 559.94 ;
      RECT 714.9 530.05 715.1 559.94 ;
      RECT 716.62 530.05 716.82 559.94 ;
      RECT 719.2 530.05 719.4 559.94 ;
      RECT 715.76 530.05 715.96 559.94 ;
      RECT 714.04 530.05 714.24 559.94 ;
      RECT 717.48 530.05 717.68 559.94 ;
      RECT 720.49 528.355 720.69 558.945 ;
      RECT 722.64 530.05 722.84 559.94 ;
      RECT 725.22 530.05 725.42 559.94 ;
      RECT 723.5 530.05 723.7 559.94 ;
      RECT 726.08 530.05 726.28 559.94 ;
      RECT 724.36 530.05 724.56 559.94 ;
      RECT 724.79 528.355 724.99 558.945 ;
      RECT 721.78 530.05 721.98 559.94 ;
      RECT 723.07 528.355 723.27 558.945 ;
      RECT 721.35 528.355 721.55 558.945 ;
      RECT 723.93 528.355 724.13 558.945 ;
      RECT 725.65 528.355 725.85 558.945 ;
      RECT 720.92 530.05 721.12 559.94 ;
      RECT 722.21 528.355 722.41 558.945 ;
      RECT 729.09 528.355 729.29 558.945 ;
      RECT 726.51 528.355 726.71 558.945 ;
      RECT 727.37 528.355 727.57 558.945 ;
      RECT 730.81 528.355 731.01 558.945 ;
      RECT 728.23 528.355 728.43 558.945 ;
      RECT 731.67 528.355 731.87 558.945 ;
      RECT 729.95 528.355 730.15 558.945 ;
      RECT 730.38 530.05 730.58 559.94 ;
      RECT 727.8 530.05 728 559.94 ;
      RECT 732.1 530.05 732.3 559.94 ;
      RECT 728.66 530.05 728.86 559.94 ;
      RECT 729.52 530.05 729.72 559.94 ;
      RECT 731.24 530.05 731.44 559.94 ;
      RECT 726.94 530.05 727.14 559.94 ;
      RECT 732.53 528.355 732.73 558.945 ;
      RECT 737.26 530.05 737.46 559.94 ;
      RECT 735.54 530.05 735.74 559.94 ;
      RECT 736.83 528.355 737.03 558.945 ;
      RECT 735.11 528.355 735.31 558.945 ;
      RECT 737.69 528.355 737.89 558.945 ;
      RECT 733.39 528.355 733.59 558.945 ;
      RECT 735.97 528.355 736.17 558.945 ;
      RECT 738.55 528.355 738.75 558.945 ;
      RECT 734.25 528.355 734.45 558.945 ;
      RECT 732.96 530.05 733.16 559.94 ;
      RECT 734.68 530.05 734.88 559.94 ;
      RECT 738.12 530.05 738.32 559.94 ;
      RECT 733.82 530.05 734.02 559.94 ;
      RECT 736.4 530.05 736.6 559.94 ;
      RECT 741.13 528.355 741.33 558.945 ;
      RECT 743.28 530.05 743.48 559.94 ;
      RECT 741.99 528.355 742.19 558.945 ;
      RECT 740.27 528.355 740.47 558.945 ;
      RECT 742.85 528.355 743.05 558.945 ;
      RECT 744.57 528.355 744.77 558.945 ;
      RECT 739.41 528.355 739.61 558.945 ;
      RECT 744.14 530.05 744.34 559.94 ;
      RECT 740.7 530.05 740.9 559.94 ;
      RECT 741.56 530.05 741.76 559.94 ;
      RECT 652.915 302.92 661.67 303.09 ;
      RECT 651.545 305.625 661.66 305.795 ;
      RECT 644.605 350.66 644.805 362.78 ;
      RECT 646.07 350.66 646.27 362.78 ;
      RECT 647.51 350.66 647.71 362.78 ;
      RECT 649.92 362.575 651.14 362.78 ;
      RECT 650.94 351.13 651.14 362.575 ;
      RECT 652.475 352.52 652.675 362.78 ;
      RECT 647.99 350.66 648.19 362.78 ;
      RECT 651.41 353.11 651.61 362.78 ;
      RECT 646.55 350.66 646.75 362.78 ;
      RECT 647.03 350.66 647.23 362.78 ;
      RECT 661.72 293.075 661.89 293.815 ;
      RECT 652.48 292.905 661.89 293.075 ;
      RECT 651.925 353.095 652.125 362.78 ;
      RECT 743.99 293.885 756.465 296.085 ;
      RECT 754.37 317.78 783.255 319.28 ;
      RECT 754.37 296.085 756.465 317.78 ;
      RECT 743.99 285.605 745.715 293.885 ;
      RECT 714.475 285.605 715.03 288.125 ;
      RECT 714.475 283.75 745.715 285.605 ;
      RECT 701.345 294.505 704.2 295.64 ;
      RECT 704.81 300.41 705.495 301.98 ;
      RECT 699.45 295.835 700.16 296.095 ;
      RECT 704.16 295.865 706.095 296.095 ;
      RECT 798.325 280.41 800.595 284.825 ;
      RECT 798.325 278.655 809.625 280.41 ;
      RECT 790.375 278.475 809.625 278.655 ;
      RECT 790.375 277.25 806.495 278.475 ;
      RECT 790.375 276.835 801.055 277.25 ;
      RECT 790.375 274.615 792.205 276.835 ;
      RECT 822.42 281.25 822.74 281.465 ;
      RECT 822.42 280.82 822.74 280.99 ;
      RECT 816.9 280.99 822.74 281.25 ;
      RECT 816.9 281.25 817.225 281.355 ;
      RECT 816.9 280.715 817.225 280.99 ;
      RECT 803.2 377.54 803.7 383.065 ;
      RECT 794.47 377.04 803.7 377.54 ;
      RECT 804.11 375.275 814.45 375.775 ;
      RECT 804.11 369.255 804.61 375.275 ;
      RECT 802.99 368.755 804.61 369.255 ;
      RECT 802.99 363.23 803.49 368.755 ;
      RECT 816.62 303.31 825.015 304.805 ;
      RECT 828.235 280.79 837.685 281.24 ;
      RECT 836.89 272.735 837.685 280.79 ;
      RECT 836.89 272.68 837.12 272.735 ;
      RECT 810.745 369.245 810.83 369.415 ;
      RECT 839.96 330.34 855.83 330.57 ;
      RECT 922.92 425.68 924.205 425.91 ;
      RECT 923.515 379.19 924.205 425.68 ;
      RECT 923.515 306.105 924 313.075 ;
      RECT 907.895 324.74 908.065 326.03 ;
      RECT 893.32 326.68 893.49 328.185 ;
      RECT 888.885 331.035 910.525 331.285 ;
      RECT 910.275 321.04 910.525 331.035 ;
      RECT 888.885 320.79 910.525 321.04 ;
      RECT 888.885 321.04 889.135 331.035 ;
      RECT 888.885 331.285 893.45 331.3 ;
      RECT 888.92 320.78 907.745 320.79 ;
      RECT 877.105 306.02 887.385 306.25 ;
      RECT 887.185 291.36 887.415 292.33 ;
      RECT 882.835 291.13 887.415 291.36 ;
      RECT 882.895 289.57 885.11 291.13 ;
      RECT 887.385 298.29 924.655 298.52 ;
      RECT 868.315 275.615 869.12 280.93 ;
      RECT 868.815 281.31 875.095 281.73 ;
      RECT 868.315 280.93 875.095 281.31 ;
      RECT 914.26 310.38 914.64 311.32 ;
      RECT 659.725 384.64 659.95 388.995 ;
      RECT 656.36 492.54 710.11 493.51 ;
      RECT 656.36 480 710.11 480.97 ;
      RECT 656.36 467.46 710.11 468.43 ;
      RECT 656.36 454.92 710.11 455.89 ;
      RECT 656.36 442.38 710.11 443.35 ;
      RECT 656.36 429.84 710.11 430.81 ;
      RECT 656.36 417.3 710.11 418.27 ;
      RECT 656.36 404.64 710.11 405.9 ;
      RECT 654.43 411.165 710.935 411.845 ;
      RECT 654.43 423.73 710.935 424.41 ;
      RECT 654.43 436.265 710.935 436.945 ;
      RECT 654.43 448.815 710.935 449.495 ;
      RECT 654.43 461.335 710.935 462.015 ;
      RECT 654.43 473.87 710.935 474.55 ;
      RECT 654.43 486.425 710.935 487.105 ;
      RECT 780.68 432.415 782.04 432.86 ;
      RECT 804.1 486.965 833.13 487.84 ;
      RECT 832.925 477.24 833.155 486.13 ;
      RECT 804.07 428.86 804.955 432.27 ;
      RECT 804.07 428.115 833.13 428.86 ;
      RECT 818.175 397.895 818.83 398.065 ;
      RECT 803.2 391.75 803.7 397.275 ;
      RECT 794.47 391.25 803.7 391.75 ;
      RECT 804.11 403.625 814.45 404.125 ;
      RECT 804.11 398.08 804.61 403.625 ;
      RECT 804.11 389.415 814.45 389.915 ;
      RECT 804.11 383.87 804.61 389.415 ;
      RECT 823.945 438.19 824.835 438.36 ;
      RECT 824.12 451.92 824.8 452.09 ;
      RECT 824.415 479.27 824.805 479.445 ;
      RECT 813.57 451.81 814.305 451.98 ;
      RECT 812 451.81 812.53 451.98 ;
      RECT 813.57 465.495 814.45 465.665 ;
      RECT 813.505 478.96 814.305 479.13 ;
      RECT 830.825 479.775 831.51 485.33 ;
      RECT 821.465 485.33 831.51 486.14 ;
      RECT 818.07 383.73 818.825 383.9 ;
      RECT 810.745 383.385 811.105 383.555 ;
      RECT 810.735 397.595 811.13 397.765 ;
      RECT 825.41 471.68 833.045 473.305 ;
      RECT 825.41 469.99 827.925 471.68 ;
      RECT 812.265 465.495 812.385 465.665 ;
      RECT 175.245 579.04 190.11 580.54 ;
      RECT 386.895 591.35 387.425 591.685 ;
      RECT 397.25 586.815 397.48 591.495 ;
      RECT 387.66 591.525 388.39 591.695 ;
      RECT 399.805 591.08 400.165 592.57 ;
      RECT 397.785 585.355 397.955 587.16 ;
      RECT 397.785 585.185 398.295 585.355 ;
      RECT 456.05 502.665 462.475 502.915 ;
      RECT 456.05 497.44 456.3 502.665 ;
      RECT 415.305 591.525 415.965 591.695 ;
      RECT 416.905 591.525 417.505 591.695 ;
      RECT 451.675 591.525 452.335 591.695 ;
      RECT 450.135 591.525 450.68 591.695 ;
      RECT 468.595 591.525 469.255 591.695 ;
      RECT 470.305 591.525 470.965 591.695 ;
      RECT 531.5 573.39 533.62 574.705 ;
      RECT 847.46 265.9 849.445 266.36 ;
      RECT 842.3 266.645 843.1 269.515 ;
      RECT 860.415 236.08 870.035 236.675 ;
      RECT 860.415 228.3 860.975 236.08 ;
      RECT 860.415 227.785 865.6 228.3 ;
      RECT 860.415 227.745 860.975 227.785 ;
      RECT 388.66 345.515 389.525 345.685 ;
      RECT 389.355 345.685 389.525 348.075 ;
      RECT 388.66 333.27 388.86 345.515 ;
      RECT 397.74 364.085 445.565 367.285 ;
      RECT 397.74 297.925 398.735 364.085 ;
      RECT 535.11 362.51 568.885 362.68 ;
      RECT 535.11 350.645 535.28 362.51 ;
      RECT 535.97 362.105 567.705 362.275 ;
      RECT 535.97 350.645 536.14 362.105 ;
      RECT 540.27 350.665 540.44 354.88 ;
      RECT 541.135 350.665 541.305 353.95 ;
      RECT 538.55 350.665 538.72 352.675 ;
      RECT 539.41 350.665 539.58 353.065 ;
      RECT 534.25 362.975 567.66 363.145 ;
      RECT 534.25 350.645 534.42 362.975 ;
      RECT 538.295 360.64 567.86 360.84 ;
      RECT 537.695 361.145 567.565 361.315 ;
      RECT 537.695 350.645 537.865 361.145 ;
      RECT 536.83 361.625 567.59 361.795 ;
      RECT 536.83 350.645 537 361.625 ;
      RECT 532.285 350.11 532.59 350.745 ;
      RECT 567.165 277.245 569.305 277.475 ;
      RECT 567.98 272.405 568.21 277.095 ;
      RECT 570.34 277.245 572.48 277.475 ;
      RECT 571.655 272.405 571.885 277.095 ;
      RECT 574.5 277.245 576.64 277.475 ;
      RECT 575.315 272.405 575.545 277.095 ;
      RECT 581.84 277.245 583.98 277.475 ;
      RECT 579 272.405 579.23 276.79 ;
      RECT 540.695 349.32 540.865 353.585 ;
      RECT 662.49 369.935 742.955 370.185 ;
      RECT 714.34 369.93 716.03 369.935 ;
      RECT 716.875 369.93 719.435 369.935 ;
      RECT 720.055 369.93 723.06 369.935 ;
      RECT 723.665 369.93 726.245 369.935 ;
      RECT 686.59 291.17 688.195 291.205 ;
      RECT 688.73 291.17 691.085 291.205 ;
      RECT 691.63 291.17 696.5 291.205 ;
      RECT 697.17 291.18 699.35 291.205 ;
      RECT 673.665 291.195 685.885 291.205 ;
      RECT 700.05 291.18 704.165 291.205 ;
      RECT 742.275 291.455 742.955 369.935 ;
      RECT 662.36 291.215 742.955 291.455 ;
      RECT 662.36 291.455 662.74 335.925 ;
      RECT 662.49 335.925 662.74 369.935 ;
      RECT 701.975 291.455 703.97 292.965 ;
      RECT 662.36 291.205 742.75 291.215 ;
      RECT 582.655 272.405 582.885 277.095 ;
      RECT 585.51 277.245 587.65 277.475 ;
      RECT 586.325 272.405 586.555 277.095 ;
      RECT 589.18 277.245 591.32 277.475 ;
      RECT 589.995 272.405 590.225 277.095 ;
      RECT 644.07 272.57 657.545 272.74 ;
      RECT 639.245 271.795 656.83 271.965 ;
      RECT 645.055 273.33 657.545 273.5 ;
      RECT 652 277.15 657.345 277.32 ;
      RECT 654.73 274.805 658.27 274.975 ;
      RECT 654.7 275.23 657.11 275.4 ;
      RECT 652.995 277.595 657.345 277.765 ;
      RECT 645.955 272.95 656.385 273.15 ;
      RECT 657.29 278.895 657.49 283.17 ;
      RECT 652.47 283.17 657.49 283.37 ;
      RECT 652.08 282.745 656.79 282.75 ;
      RECT 652.08 282.55 656.83 282.745 ;
      RECT 656.63 278.71 656.83 282.55 ;
      RECT 652.585 281.99 656.3 282.19 ;
      RECT 656.1 278.355 656.3 281.99 ;
      RECT 656.1 278.155 658.715 278.355 ;
      RECT 655.335 274.39 656.22 274.56 ;
      RECT 655.335 273.935 655.505 274.39 ;
      RECT 654.365 273.765 655.505 273.935 ;
      RECT 624.79 350.745 624.99 362.76 ;
      RECT 626.255 350.745 626.455 362.76 ;
      RECT 636.355 350.745 636.555 362.76 ;
      RECT 630.595 350.745 630.795 362.76 ;
      RECT 638.275 350.745 638.475 362.76 ;
      RECT 627.215 350.745 627.415 362.76 ;
      RECT 631.075 350.745 631.275 362.76 ;
      RECT 637.795 350.745 637.995 362.76 ;
      RECT 641.725 350.745 641.925 362.76 ;
      RECT 626.735 350.745 626.935 362.76 ;
      RECT 644.125 350.66 644.325 362.78 ;
      RECT 628.175 350.745 628.375 362.76 ;
      RECT 628.655 350.745 628.855 362.76 ;
      RECT 640.285 350.745 640.485 362.76 ;
      RECT 639.715 350.745 639.915 362.76 ;
      RECT 625.775 350.745 625.975 362.76 ;
      RECT 637.315 350.745 637.515 362.76 ;
      RECT 630.095 350.745 630.295 362.76 ;
      RECT 625.27 350.745 625.47 362.76 ;
      RECT 634.915 350.745 635.115 362.76 ;
      RECT 641.245 350.745 641.445 362.76 ;
      RECT 643.165 350.745 643.365 362.76 ;
      RECT 635.395 350.745 635.595 362.76 ;
      RECT 640.765 350.745 640.965 362.76 ;
      RECT 643.645 350.745 643.845 362.76 ;
      RECT 634.435 350.745 634.635 362.76 ;
      RECT 627.695 350.745 627.895 362.76 ;
      RECT 638.755 350.745 638.955 362.76 ;
      RECT 623.83 350.745 624.03 362.76 ;
      RECT 633.475 350.745 633.675 362.76 ;
      RECT 631.555 350.745 631.755 362.76 ;
      RECT 636.835 350.745 637.035 362.76 ;
      RECT 632.995 350.745 633.195 362.76 ;
      RECT 639.235 350.745 639.435 362.76 ;
      RECT 633.955 350.745 634.155 362.76 ;
      RECT 632.515 350.745 632.715 362.76 ;
      RECT 632.035 350.745 632.235 362.76 ;
      RECT 642.685 350.745 642.885 362.76 ;
      RECT 623.35 350.745 623.55 362.76 ;
      RECT 642.205 350.745 642.405 362.76 ;
      RECT 624.31 350.745 624.51 362.76 ;
      RECT 622.87 350.745 623.07 362.76 ;
      RECT 635.875 350.745 636.075 362.76 ;
      RECT 657.905 350.99 658.105 362.505 ;
      RECT 654.035 362.505 658.105 362.74 ;
      RECT 654.035 362.74 658.1 362.745 ;
      RECT 651.925 350.765 658.105 350.99 ;
      RECT 651.925 349.805 652.125 350.765 ;
      RECT 645.11 350.66 645.31 362.78 ;
      RECT 645.59 350.66 645.79 362.78 ;
      RECT 625.57 148.585 625.8 148.93 ;
      RECT 625.57 148.355 632.25 148.585 ;
      RECT 625.575 149.735 625.805 158.095 ;
      RECT 632.02 145.965 632.25 148.355 ;
      RECT 625.61 158.095 625.78 161.585 ;
      RECT 625.61 148.93 625.78 149.735 ;
      RECT 632.055 145.6 632.225 145.965 ;
      RECT 626.555 149.465 626.785 158.095 ;
      RECT 632.885 146.035 633.115 149.23 ;
      RECT 626.59 158.095 626.76 161.235 ;
      RECT 626.555 149.235 627.44 149.255 ;
      RECT 631.495 149.425 633.115 149.46 ;
      RECT 632.915 145.6 633.085 146.035 ;
      RECT 631.495 149.23 633.115 149.255 ;
      RECT 626.555 149.425 627.44 149.465 ;
      RECT 626.555 149.255 633.115 149.425 ;
      RECT 635.875 145.355 636.075 158.98 ;
      RECT 636.355 145.355 636.555 158.98 ;
      RECT 635.395 145.355 635.595 158.98 ;
      RECT 638.505 148.52 644.84 148.72 ;
      RECT 638.505 145.525 638.705 148.52 ;
      RECT 644.64 148.72 644.84 158.79 ;
      RECT 639.655 145.49 639.825 147.195 ;
      RECT 639.655 147.195 646.27 147.365 ;
      RECT 646.07 147.365 646.27 157.43 ;
      RECT 655.325 155.685 657.025 155.885 ;
      RECT 656.855 145.245 657.025 155.685 ;
      RECT 655.325 155.885 655.525 160.66 ;
      RECT 654.175 145.245 654.345 147.025 ;
      RECT 653.885 147.025 654.345 147.225 ;
      RECT 653.885 147.225 654.085 160.66 ;
      RECT 655.085 145.245 655.255 148.175 ;
      RECT 654.365 148.175 655.255 148.375 ;
      RECT 654.365 148.375 654.565 160.66 ;
      RECT 638.895 148.05 645.31 148.22 ;
      RECT 638.895 145.49 639.065 148.05 ;
      RECT 645.11 148.22 645.31 157.43 ;
      RECT 647.03 145.825 647.23 157.43 ;
      RECT 654.845 154.865 656.155 155.065 ;
      RECT 655.985 145.245 656.155 154.865 ;
      RECT 654.845 155.065 655.045 160.66 ;
      RECT 647.99 146.8 648.19 157.43 ;
      RECT 715.99 124.835 744.97 127.835 ;
      RECT 676.895 159.885 680.89 160.15 ;
      RECT 397.745 212.285 398.635 234.465 ;
      RECT 397.745 211.18 399.49 212.285 ;
      RECT 414.335 164.785 451.005 165.285 ;
      RECT 446.16 165.505 450.04 165.735 ;
      RECT 401.885 165.51 405.765 165.74 ;
      RECT 492.4 204.5 504.4 204.73 ;
      RECT 504.17 204.23 504.4 204.5 ;
      RECT 492.415 204 504.4 204.23 ;
      RECT 492.415 203.695 492.645 204 ;
      RECT 492.415 203.465 504.405 203.695 ;
      RECT 492.345 205.205 492.575 207.67 ;
      RECT 492.345 204.975 504.55 205.205 ;
      RECT 504.32 205.205 504.55 210.825 ;
      RECT 492.34 222.75 504.555 222.98 ;
      RECT 492.34 218.225 492.57 222.75 ;
      RECT 504.325 213.935 504.555 222.75 ;
      RECT 493.435 185.935 530.45 186.165 ;
      RECT 493.05 202.97 530.79 203.2 ;
      RECT 493.05 168.69 493.28 202.97 ;
      RECT 530.56 168.69 530.79 202.97 ;
      RECT 493.05 168.46 530.79 168.69 ;
      RECT 650.035 193.665 657.665 193.835 ;
      RECT 648.955 194.425 657.665 194.595 ;
      RECT 649.925 195.185 657.665 195.355 ;
      RECT 648.085 195.945 657.665 196.115 ;
      RECT 647.12 196.705 657.665 196.875 ;
      RECT 651.985 269.86 660.355 270.03 ;
      RECT 660.155 270.03 660.355 277.225 ;
      RECT 640.785 270.655 657.565 270.825 ;
      RECT 656.275 197.355 656.885 197.465 ;
      RECT 638.865 197.465 656.885 197.635 ;
      RECT 638.32 198.225 655.76 198.395 ;
      RECT 655.59 197.995 655.76 198.225 ;
      RECT 655.59 197.825 656.485 197.995 ;
      RECT 637.88 198.985 656.185 199.155 ;
      RECT 656.015 198.45 656.185 198.985 ;
      RECT 656.015 198.28 656.435 198.45 ;
      RECT 637.33 199.745 657.12 199.915 ;
      RECT 656.95 198.725 657.12 199.745 ;
      RECT 656.95 198.555 658.355 198.725 ;
      RECT 661.75 269.655 661.95 277.225 ;
      RECT 652.415 269.485 661.95 269.655 ;
      RECT 641.26 270.275 656.83 270.445 ;
      RECT 640.305 271.035 658.44 271.205 ;
      RECT 639.73 271.415 657.76 271.585 ;
      RECT 654.85 265.7 656.04 266.535 ;
      RECT 653.36 261.935 654.55 262.77 ;
      RECT 589.715 164.185 593.855 166.045 ;
      RECT 707.255 269.945 707.425 277.795 ;
      RECT 700.415 269.845 700.585 277.32 ;
      RECT 699.25 268.815 699.39 270.045 ;
      RECT 800.195 249.24 800.425 262.845 ;
      RECT 800.195 269.32 800.365 269.865 ;
      RECT 812.27 226.525 824.535 227.205 ;
      RECT 828.2 227.32 840.545 227.505 ;
      RECT 828.2 227.07 843.465 227.32 ;
      RECT 828.2 232 828.695 233.02 ;
      RECT 828.2 227.505 828.685 231.77 ;
      RECT 828.2 231.77 839.43 232 ;
      RECT 847.855 238.265 854.855 238.35 ;
      RECT 828.2 238.495 848.44 238.83 ;
      RECT 828.2 238.83 828.685 254.28 ;
      RECT 828.2 233.02 828.685 238.35 ;
      RECT 828.2 238.35 854.855 238.495 ;
      RECT 854.705 242.215 854.935 246.47 ;
      RECT 817.75 254.26 818.065 254.315 ;
      RECT 817.75 253.655 818.065 254.09 ;
      RECT 817.75 254.09 821.96 254.26 ;
      RECT 821.645 254.26 821.96 254.315 ;
      RECT 821.645 253.655 821.96 254.09 ;
      RECT 817.75 255.15 818.065 255.39 ;
      RECT 817.75 254.73 818.065 254.98 ;
      RECT 817.75 254.98 821.96 255.15 ;
      RECT 821.645 255.15 821.96 255.39 ;
      RECT 821.645 254.73 821.96 254.98 ;
      RECT 813.16 217.27 816.695 225.765 ;
      RECT 823.685 266.605 824 266.755 ;
      RECT 823.685 266.095 824 266.31 ;
      RECT 817.785 266.31 824 266.605 ;
      RECT 817.785 266.605 818.1 266.78 ;
      RECT 817.785 266.105 818.1 266.31 ;
      RECT 842.29 269.515 848.105 270.06 ;
      RECT 847.46 266.36 848.105 269.515 ;
      RECT 650.465 293.8 653.11 293.97 ;
      RECT 752.13 293.22 752.3 293.64 ;
      RECT 650.465 291.105 650.635 293.8 ;
      RECT 650.465 290.935 653.11 291.105 ;
      RECT 652.94 284.14 653.11 290.935 ;
      RECT 651.525 283.97 658.1 284.14 ;
      RECT 657.925 281.64 752.3 281.81 ;
      RECT 751.94 281.81 752.3 293.22 ;
      RECT 736.22 281.81 743.565 281.845 ;
      RECT 721.21 281.81 729.885 281.845 ;
      RECT 711.085 281.81 719.41 281.845 ;
      RECT 744.545 281.81 749.94 281.84 ;
      RECT 736.22 281.615 743.565 281.64 ;
      RECT 721.21 281.615 729.885 281.64 ;
      RECT 711.085 281.615 719.41 281.64 ;
      RECT 744.545 281.61 749.94 281.64 ;
      RECT 657.93 281.81 658.1 283.97 ;
      RECT 662.155 281.81 685.785 281.84 ;
      RECT 686.82 281.81 706.32 281.84 ;
      RECT 662.155 281.61 685.785 281.64 ;
      RECT 686.82 281.61 706.32 281.64 ;
      RECT 653.32 281.64 655.725 281.81 ;
      RECT 811.56 224.62 811.79 347.34 ;
      RECT 651.525 281.365 651.695 283.97 ;
      RECT 653.32 281.365 653.49 281.64 ;
      RECT 651.525 281.195 653.49 281.365 ;
      RECT 811.59 220.48 811.76 224.62 ;
      RECT 811.56 215.23 811.79 220.48 ;
      RECT 811.56 215.2 812.285 215.23 ;
      RECT 817.36 215.2 821.32 215.23 ;
      RECT 861.12 215.2 926.135 215.23 ;
      RECT 930.025 215.2 933.49 215.23 ;
      RECT 811.56 215.03 933.49 215.2 ;
      RECT 811.56 215 812.285 215.03 ;
      RECT 817.36 215 821.32 215.03 ;
      RECT 861.12 215 926.135 215.03 ;
      RECT 930.025 215 933.49 215.03 ;
      RECT 933.26 128.29 933.49 215 ;
      RECT 933.29 124.33 933.46 128.29 ;
      RECT 29.675 55.575 29.905 342.215 ;
      RECT 29.705 55.155 29.875 55.575 ;
      RECT 31.02 55.155 36.175 55.185 ;
      RECT 38.53 55.155 41.195 55.185 ;
      RECT 52.155 55.155 64.94 55.185 ;
      RECT 29.705 54.985 41.455 55.155 ;
      RECT 46.515 54.985 64.94 55.155 ;
      RECT 31.02 54.955 36.175 54.985 ;
      RECT 38.53 54.955 41.195 54.985 ;
      RECT 52.155 54.955 64.94 54.985 ;
      RECT 64.71 38.83 64.94 54.955 ;
      RECT 64.74 37.77 64.91 38.83 ;
      RECT 64.71 33.265 64.94 37.77 ;
      RECT 933.26 28.745 933.49 124.33 ;
      RECT 251.485 28.715 530.89 28.745 ;
      RECT 251.485 28.515 530.89 28.545 ;
      RECT 64.74 28.545 933.49 28.715 ;
      RECT 537.51 28.715 933.49 28.745 ;
      RECT 537.51 28.515 933.49 28.545 ;
      RECT 64.74 28.715 64.91 33.265 ;
      RECT 64.74 24.705 250.895 28.545 ;
      RECT 64.74 24.475 251.05 24.705 ;
      RECT 177.005 104.975 275.705 106.25 ;
      RECT 545.06 592.045 696.485 592.275 ;
      RECT 790.105 559.875 926.215 560.125 ;
      RECT 790.105 497.845 790.51 559.875 ;
      RECT 925.965 497.845 926.215 559.875 ;
      RECT 790.105 497.595 926.215 497.845 ;
      RECT 840.515 497.845 846.265 497.855 ;
      RECT 68.265 38.075 234.405 38.365 ;
      RECT 383.315 583.525 388.755 585.35 ;
      RECT 383.315 582.075 489.48 583.525 ;
      RECT 465.56 583.525 467.62 584.96 ;
      RECT 412.27 583.525 417.71 584.88 ;
      RECT 450.145 583.525 455.585 584.88 ;
      RECT 474.82 583.525 480.26 584.88 ;
      RECT 503.94 582.075 682.375 583.37 ;
      RECT 557.205 583.37 587.68 585.02 ;
      RECT 610.735 583.37 619.79 585.305 ;
      RECT 641.125 583.37 646.565 584.88 ;
      RECT 15.645 18.65 18.645 602.73 ;
      RECT 15.645 15.65 946.62 18.65 ;
      RECT 943.62 18.65 946.62 602.73 ;
      RECT 15.645 602.73 946.62 605.73 ;
      RECT 44.295 54.985 45.4 55.155 ;
      RECT 42.9 54.985 43.66 55.155 ;
      RECT 361.045 112.795 431.25 113.105 ;
      RECT 361.045 119.645 431.25 119.955 ;
      RECT 411.07 129.075 411.24 158.015 ;
      RECT 381.75 128.905 411.24 129.075 ;
      RECT 381.75 158.015 411.24 158.185 ;
      RECT 381.75 129.075 381.92 158.015 ;
      RECT 444.385 130.45 447.885 150.155 ;
      RECT 429.525 126.51 434.795 127.92 ;
      RECT 568.34 152.145 568.51 159.04 ;
      RECT 574.605 147.21 574.775 160.455 ;
      RECT 575.675 146.225 575.875 159.69 ;
      RECT 548.79 145.97 548.99 157.485 ;
      RECT 547.93 145.97 548.13 158.375 ;
      RECT 547.07 145.97 547.27 159.2 ;
      RECT 547.5 145.97 547.7 158.825 ;
      RECT 548.36 145.97 548.56 157.935 ;
      RECT 603.425 143.175 627.41 144.685 ;
      RECT 605.035 144.685 609.06 144.87 ;
      RECT 596.795 152.12 596.965 158.99 ;
      RECT 594.87 145.37 595.04 152.19 ;
      RECT 593.6 150.1 593.77 162.85 ;
      RECT 598.67 145.665 598.84 156.645 ;
      RECT 599.43 145.665 599.6 157.13 ;
      RECT 600.19 145.665 600.36 157.515 ;
      RECT 600.95 145.665 601.12 158.015 ;
      RECT 593 151.155 593.17 163.685 ;
      RECT 637.795 152.165 637.995 158.81 ;
      RECT 638.145 148.99 644.325 149.16 ;
      RECT 638.145 145.49 638.315 148.99 ;
      RECT 644.125 149.16 644.325 157.43 ;
      RECT 626.09 148.85 632.655 149.02 ;
      RECT 632.485 145.6 632.655 148.85 ;
      RECT 626.09 149.02 626.26 162.095 ;
      RECT 627.195 149.935 627.365 161.235 ;
      RECT 627.215 149.765 633.515 149.835 ;
      RECT 633.345 145.6 633.515 149.765 ;
      RECT 627.195 149.835 633.515 149.935 ;
      RECT 627.885 150.265 634.285 150.765 ;
      RECT 633.78 145.065 634.285 150.265 ;
      RECT 627.885 150.765 628.4 161.235 ;
      RECT 636.835 145.355 637.035 158.98 ;
      RECT 634.915 145.355 635.115 158.98 ;
      RECT 543.16 577.33 632.69 577.36 ;
      RECT 534.805 577.33 539.23 577.36 ;
      RECT 637.345 577.33 654.575 577.36 ;
      RECT 658.71 577.33 692.765 577.36 ;
      RECT 695.39 577.33 698.365 577.36 ;
      RECT 701.975 577.33 703.77 577.36 ;
      RECT 204.715 577.33 253.275 577.36 ;
      RECT 391.565 577.33 399.105 577.36 ;
      RECT 403.19 577.33 407.085 577.36 ;
      RECT 665.095 564.625 672.78 577.33 ;
      RECT 639.48 564.625 654.5 564.66 ;
      RECT 632.475 564.625 633.33 564.655 ;
      RECT 639.48 564.43 654.5 564.455 ;
      RECT 632.475 564.455 698.285 564.625 ;
      RECT 632.475 564.425 633.33 564.455 ;
      RECT 161.025 562.29 161.195 592.96 ;
      RECT 28.635 562.29 82.235 562.32 ;
      RECT 86.135 562.29 129.74 562.32 ;
      RECT 28.635 562.12 161.195 562.29 ;
      RECT 28.635 562.09 82.235 562.12 ;
      RECT 86.135 562.09 129.74 562.12 ;
      RECT 698.115 556.205 698.285 564.455 ;
      RECT 28.635 554.085 28.865 562.09 ;
      RECT 28.665 541.29 28.835 554.085 ;
      RECT 698.085 527.475 698.315 556.205 ;
      RECT 698.085 527.44 704.51 527.475 ;
      RECT 698.085 527.245 716.485 527.44 ;
      RECT 698.135 526.68 716.485 527.245 ;
      RECT 632.475 517.02 632.705 564.425 ;
      RECT 632.51 511.015 632.68 517.02 ;
      RECT 632.51 510.925 650.245 511.015 ;
      RECT 632.51 510.845 650.265 510.925 ;
      RECT 714.65 496.385 716.485 526.68 ;
      RECT 766.01 479.595 766.81 577.33 ;
      RECT 766.295 476.845 766.525 479.595 ;
      RECT 766.325 475.525 766.495 476.845 ;
      RECT 766.295 470.675 766.525 475.525 ;
      RECT 766.325 468.21 766.495 470.675 ;
      RECT 766.295 461.51 766.525 468.21 ;
      RECT 766.325 456.445 766.495 461.51 ;
      RECT 766.295 439.44 766.525 456.445 ;
      RECT 766.325 438.29 766.495 439.44 ;
      RECT 766.295 433.55 766.525 438.29 ;
      RECT 766.325 429.62 766.495 433.55 ;
      RECT 766.295 428.825 766.525 429.62 ;
      RECT 766.325 428.225 766.495 428.825 ;
      RECT 766.295 427.5 766.525 428.225 ;
      RECT 650.035 427.785 650.265 510.845 ;
      RECT 766.325 424.905 766.495 427.5 ;
      RECT 766.29 423.12 766.52 424.905 ;
      RECT 766.325 421.74 766.495 423.12 ;
      RECT 714.485 404.91 716.485 496.385 ;
      RECT 714.62 398.125 716.485 404.91 ;
      RECT 704.595 398.065 710.215 398.1 ;
      RECT 704.595 397.87 710.215 397.895 ;
      RECT 650.075 397.895 716.485 398.065 ;
      RECT 766.295 397.1 766.525 421.74 ;
      RECT 711.295 398.065 716.485 398.125 ;
      RECT 650.075 398.065 650.245 427.785 ;
      RECT 660.31 398.065 701.21 398.1 ;
      RECT 660.31 397.87 701.21 397.895 ;
      RECT 766.325 385.81 766.495 397.1 ;
      RECT 28.665 380.29 30.74 541.29 ;
      RECT 715.325 379.775 752.615 380.06 ;
      RECT 680.2 379.775 682.955 380.23 ;
      RECT 704.575 379.745 752.615 379.775 ;
      RECT 662.51 379.745 673.855 379.775 ;
      RECT 675.445 379.745 686.79 379.775 ;
      RECT 689.83 379.745 701.175 379.775 ;
      RECT 654.25 379.745 658.06 379.765 ;
      RECT 704.575 379.545 752.615 379.575 ;
      RECT 652.94 379.575 752.615 379.745 ;
      RECT 675.445 379.545 680.43 379.575 ;
      RECT 682.725 379.545 686.79 379.575 ;
      RECT 662.51 379.545 673.855 379.575 ;
      RECT 689.83 379.545 701.175 379.575 ;
      RECT 654.25 379.535 658.06 379.575 ;
      RECT 715.325 379.26 752.615 379.545 ;
      RECT 28.665 377.795 28.835 380.29 ;
      RECT 34.69 377.795 108.675 377.825 ;
      RECT 110.04 377.795 126.405 377.825 ;
      RECT 138.83 377.795 155.49 377.825 ;
      RECT 127.935 377.795 137.81 377.825 ;
      RECT 156.905 377.795 183.805 377.825 ;
      RECT 28.665 377.625 183.805 377.795 ;
      RECT 766.295 364.165 766.525 385.81 ;
      RECT 34.69 377.595 108.675 377.625 ;
      RECT 110.04 377.595 126.405 377.625 ;
      RECT 138.83 377.595 155.49 377.625 ;
      RECT 127.935 377.595 137.81 377.625 ;
      RECT 156.905 377.595 183.805 377.625 ;
      RECT 766.325 362.31 766.495 364.165 ;
      RECT 652.94 351.51 653.11 379.575 ;
      RECT 651.425 351.34 653.11 351.51 ;
      RECT 766.295 349.48 766.525 362.31 ;
      RECT 651.425 349.09 651.595 351.34 ;
      RECT 652.94 349.09 653.11 350.495 ;
      RECT 651.425 348.92 653.11 349.09 ;
      RECT 751.815 347.87 752.615 379.26 ;
      RECT 766.325 347.87 766.495 349.48 ;
      RECT 751.815 347.54 766.495 347.87 ;
      RECT 769.765 347.54 774.915 347.57 ;
      RECT 782.07 347.54 811.79 347.57 ;
      RECT 751.815 347.37 811.79 347.54 ;
      RECT 769.765 347.34 774.915 347.37 ;
      RECT 782.07 347.34 811.79 347.37 ;
      RECT 183.575 342.445 183.805 377.595 ;
      RECT 52.31 342.415 183.805 342.445 ;
      RECT 29.675 342.415 42.02 342.445 ;
      RECT 45.275 342.415 50.865 342.445 ;
      RECT 29.675 342.245 183.805 342.415 ;
      RECT 52.31 342.215 183.805 342.245 ;
      RECT 29.675 342.215 42.02 342.245 ;
      RECT 45.275 342.215 50.865 342.245 ;
      RECT 751.815 322.175 752.615 347.37 ;
      RECT 652.5 306.705 653.11 348.92 ;
      RECT 652.94 306.105 653.11 306.535 ;
      RECT 650.93 306.535 653.11 306.705 ;
      RECT 650.93 304.54 651.1 306.535 ;
      RECT 652.94 304.54 653.11 305.32 ;
      RECT 652.94 303.67 653.11 304.37 ;
      RECT 650.93 304.37 653.11 304.54 ;
      RECT 650.93 302.315 651.1 304.37 ;
      RECT 751.94 296.555 752.3 322.175 ;
      RECT 650.93 302.31 653.025 302.315 ;
      RECT 650.93 302.145 653.11 302.31 ;
      RECT 652.94 293.97 653.11 302.145 ;
      RECT 531.505 77.14 539.525 80.755 ;
      RECT 738.57 34.56 744.965 39.51 ;
      RECT 536.82 33.81 744.965 34.56 ;
      RECT 536.82 34.56 539.525 77.14 ;
      RECT 536.82 31.645 744.96 33.81 ;
      RECT 475.56 158.575 509.17 163.76 ;
      RECT 475.56 130.52 480.085 158.575 ;
      RECT 475.56 347.79 480.085 347.87 ;
      RECT 465.985 322.245 480.085 347.79 ;
      RECT 475.56 260.45 480.085 322.245 ;
      RECT 475.56 163.76 480.085 234.905 ;
      RECT 465.985 234.905 480.085 260.45 ;
      RECT 829.965 330.44 834.01 330.67 ;
      RECT 768.28 566.765 769.78 579.04 ;
      RECT 703.575 579.04 769.78 580.54 ;
      RECT 401.94 593.925 705.075 595.425 ;
      RECT 813.205 317.78 930.4 319.28 ;
      RECT 929.39 319.28 930.4 325.03 ;
      RECT 768.28 565.265 797.53 565.39 ;
      RECT 928.9 524.415 929.13 524.42 ;
      RECT 703.575 579.03 705.075 579.04 ;
      RECT 703.575 580.54 705.075 593.925 ;
      RECT 401.94 592.61 405.43 593.925 ;
      RECT 536.41 592.61 542.125 593.925 ;
      RECT 830.705 319.28 833.19 330.44 ;
      RECT 797.105 566.765 930.4 566.895 ;
      RECT 929.39 524.415 930.4 565.39 ;
      RECT 768.28 565.39 930.4 566.765 ;
      RECT 928.765 325.03 930.4 524.415 ;
      RECT 826.12 219.33 827.655 278.325 ;
      RECT 21.425 597.715 941.595 600.715 ;
      RECT 826.12 278.325 827.715 281.735 ;
      RECT 21.425 23.665 24.425 597.715 ;
      RECT 826.12 281.735 851.905 282.995 ;
      RECT 21.425 20.665 941.595 23.665 ;
      RECT 829.445 282.995 838.595 283.75 ;
      RECT 685.765 580.54 694.545 584.85 ;
      RECT 838.96 273.4 846.015 273.8 ;
      RECT 845.615 271.23 846.015 273.4 ;
      RECT 845.615 270.83 850.5 271.23 ;
      RECT 826.12 218.52 941.595 219.33 ;
      RECT 938.595 219.6 941.595 597.715 ;
      RECT 924.43 219.33 941.595 219.6 ;
      RECT 838.96 273.8 839.36 281.735 ;
      RECT 57.305 584.135 61.3 597.715 ;
      RECT 57.305 579.05 65.205 584.135 ;
      RECT 191.9 579.04 694.54 580.54 ;
      RECT 499.545 584.85 533.57 585.275 ;
      RECT 490.77 580.54 499.55 584.25 ;
      RECT 490.77 584.25 533.57 584.85 ;
      RECT 938.595 23.665 941.595 218.52 ;
      RECT 360.175 580.54 366.25 597.715 ;
      RECT 847.525 487.72 926.15 489.505 ;
      RECT 925.135 383.53 925.895 410.615 ;
      RECT 925.15 410.615 925.895 487.72 ;
      RECT 925.15 360.005 925.895 383.53 ;
      RECT 161.025 592.96 191.505 593.13 ;
      RECT 408.19 577.53 533.73 577.56 ;
      RECT 758.39 577.53 766.81 577.56 ;
      RECT 710.84 577.53 712.765 577.56 ;
      RECT 752.315 577.53 757.23 577.56 ;
      RECT 543.16 577.53 632.69 577.56 ;
      RECT 534.805 577.53 539.23 577.56 ;
      RECT 637.345 577.53 654.575 577.56 ;
      RECT 658.71 577.53 692.765 577.56 ;
      RECT 695.39 577.53 698.365 577.56 ;
      RECT 701.975 577.53 703.77 577.56 ;
      RECT 191.335 577.53 191.505 592.96 ;
      RECT 204.715 577.53 253.275 577.56 ;
      RECT 391.565 577.53 399.105 577.56 ;
      RECT 403.19 577.53 407.085 577.56 ;
      RECT 191.335 577.36 766.81 577.53 ;
      RECT 408.19 577.33 533.73 577.36 ;
      RECT 758.39 577.33 766.81 577.36 ;
      RECT 710.84 577.33 712.765 577.36 ;
      RECT 752.315 577.33 757.23 577.36 ;
      RECT 0 0 15 621.385 ;
      RECT 947.27 0 962.27 621.385 ;
      RECT 15 0 947.27 15 ;
      RECT 15 606.385 947.27 621.385 ;
    LAYER met1 ;
      RECT 15.14 550.57 30.86 550.625 ;
      RECT 15.14 549.45 30.86 549.455 ;
      RECT 15.14 549.65 30.86 549.655 ;
      RECT 32.465 550.57 707.54 553.575 ;
      RECT 15 597.01 698.385 606.385 ;
      RECT 15.3 568.225 32.385 568.27 ;
      RECT 15 15 947.27 347.555 ;
      RECT 30.725 347.555 947.27 348.315 ;
      RECT 30.725 348.315 947.27 348.515 ;
      RECT 15 349.275 947.27 353.83 ;
      RECT 30.725 353.83 947.27 354.59 ;
      RECT 30.725 348.515 947.27 349.275 ;
      RECT 15 519.75 707.54 548.22 ;
      RECT 31.14 548.22 707.54 549.455 ;
      RECT 31.14 549.455 707.54 549.65 ;
      RECT 15 593.62 480.99 597.01 ;
      RECT 33.645 568.225 698.385 568.935 ;
      RECT 33.53 568.935 698.385 569.695 ;
      RECT 15 569.695 698.385 593.62 ;
      RECT 33.53 568.935 698.385 593.62 ;
      RECT 33.53 568.935 698.385 593.62 ;
      RECT 33.53 568.935 698.385 593.62 ;
      RECT 488.04 593.62 698.385 595.63 ;
      RECT 488.04 569.695 698.385 595.63 ;
      RECT 15 354.59 947.27 519.75 ;
      RECT 30.725 349.275 947.27 519.75 ;
      RECT 709.77 559.87 712.9 606.385 ;
      RECT 709.77 519.75 712.9 606.385 ;
      RECT 709.77 558.765 713.33 559.87 ;
      RECT 709.77 519.75 713.33 559.87 ;
      RECT 709.77 519.75 947.27 558.765 ;
      RECT 751.93 573.37 825.965 606.385 ;
      RECT 751.93 565.11 907.93 567.15 ;
      RECT 751.93 558.765 907.93 567.15 ;
      RECT 831.045 573.37 904.28 606.385 ;
      RECT 751.93 567.15 913.52 573.37 ;
      RECT 907.96 573.37 913.52 606.385 ;
      RECT 751.93 558.765 947.27 565.11 ;
      RECT 919.055 565.11 947.27 606.385 ;
      RECT 32.5 549.65 707.54 550.415 ;
      RECT 33.645 559.435 698.385 569.695 ;
      RECT 33.645 559.435 698.385 568.935 ;
      RECT 33.645 559.435 698.385 568.935 ;
      RECT 701.935 559.435 707.54 606.385 ;
      RECT 701.935 551.27 707.54 606.385 ;
      RECT 15 559.435 698.385 568.225 ;
      RECT 15 551.27 707.54 559.435 ;
      RECT 15.3 559.435 32.385 568.27 ;
      RECT 15.3 559.435 32.385 568.27 ;
      RECT 15.3 559.435 32.385 568.27 ;
      RECT 15.31 568.885 32.41 569.035 ;
      RECT 719.25 558.765 720.21 559.23 ;
      RECT 15 348.315 30.725 348.515 ;
      RECT 15 550.415 707.54 550.57 ;
      RECT 15 549.455 31.14 549.65 ;
      RECT 15.125 551.22 30.86 554.225 ;
      RECT 0 0 6.9 340.885 ;
      RECT 0 361.26 6.9 541.55 ;
      RECT 0 557.94 6.9 561.555 ;
      RECT 0 576.365 6.9 621.385 ;
      RECT 6.9 0 15 340.885 ;
      RECT 6.9 361.26 15 541.55 ;
      RECT 6.9 557.94 15 561.555 ;
      RECT 6.9 576.365 15 621.385 ;
      RECT 947.27 0 962.27 621.385 ;
      RECT 15 0 947.27 15 ;
      RECT 15 606.385 691.765 621.385 ;
      RECT 758.55 606.385 819.345 621.385 ;
      RECT 837.665 606.385 897.66 621.385 ;
      RECT 925.675 606.385 947.27 621.385 ;
    LAYER met2 ;
      RECT 20.06 540.905 947.27 544.53 ;
      RECT 20.06 535.91 932.41 536.67 ;
      RECT 20.06 549.74 947.27 553.23 ;
      RECT 20.06 548.98 932.41 549.74 ;
      RECT 20.06 545.29 932.41 549.74 ;
      RECT 20.06 545.29 947.27 548.98 ;
      RECT 20.06 540.905 932.41 548.98 ;
      RECT 20.06 544.53 932.41 545.29 ;
      RECT 20.06 381.99 947.27 410.67 ;
      RECT 20.06 347.91 928.63 410.67 ;
      RECT 20.06 427.14 947.27 479.62 ;
      RECT 20.06 411.49 928.57 479.62 ;
      RECT 20.06 426.26 928.57 427.14 ;
      RECT 20.06 411.49 947.27 426.26 ;
      RECT 20.06 381.99 928.55 426.26 ;
      RECT 20.06 410.67 928.55 411.49 ;
      RECT 20.06 479.62 931.72 480.32 ;
      RECT 20.06 532.37 932.41 540.145 ;
      RECT 20.06 532.37 947.27 535.91 ;
      RECT 20.06 531.61 932.41 532.37 ;
      RECT 20.06 489.25 932.41 532.37 ;
      RECT 20.06 489.25 941.795 531.61 ;
      RECT 20.06 487.685 928.405 489.25 ;
      RECT 20.06 480.32 928.405 531.61 ;
      RECT 20.06 480.32 928.405 531.61 ;
      RECT 20.06 480.32 928.405 531.61 ;
      RECT 20.06 487.045 928.555 487.685 ;
      RECT 20.06 480.32 928.555 487.685 ;
      RECT 20.06 480.32 928.555 487.685 ;
      RECT 20.06 480.32 928.555 487.685 ;
      RECT 20.06 486.285 928.61 487.045 ;
      RECT 20.06 480.32 928.61 487.045 ;
      RECT 20.06 480.32 928.61 487.045 ;
      RECT 20.06 480.32 928.61 487.045 ;
      RECT 20.06 480.32 947.27 486.285 ;
      RECT 20.06 427.14 931.72 486.285 ;
      RECT 15 49.03 644.6 60.145 ;
      RECT 43.675 111.935 947.27 114.285 ;
      RECT 15 87.95 947.27 111.935 ;
      RECT 20.06 60.145 644.6 77.25 ;
      RECT 43.675 85.6 947.27 87.95 ;
      RECT 20.06 553.23 932.41 553.99 ;
      RECT 20.06 553.99 947.27 554.075 ;
      RECT 395.195 163.405 947.27 163.885 ;
      RECT 396.055 163.885 947.27 164.365 ;
      RECT 396.14 164.365 947.27 165.125 ;
      RECT 20.06 77.25 947.27 85.6 ;
      RECT 43.675 77.25 947.27 87.95 ;
      RECT 648.06 31.67 796.99 39.875 ;
      RECT 15 15 947.27 25.11 ;
      RECT 648.06 39.875 947.27 77.25 ;
      RECT 803.08 25.11 947.27 26.205 ;
      RECT 803.095 26.205 947.27 39.875 ;
      RECT 803.095 25.11 947.27 39.875 ;
      RECT 15 135.275 947.27 139.005 ;
      RECT 15 131.325 938.085 135.275 ;
      RECT 15 128.71 938.085 130.555 ;
      RECT 15 128.115 938.085 128.71 ;
      RECT 15 114.285 947.27 124.555 ;
      RECT 43.675 87.95 947.27 124.555 ;
      RECT 15 39.765 644.6 43.67 ;
      RECT 26.335 43.67 644.6 49.03 ;
      RECT 239.775 31.67 644.6 43.67 ;
      RECT 239.775 31.67 644.6 39.61 ;
      RECT 180.665 554.075 947.27 557.22 ;
      RECT 180.665 553.99 947.27 557.22 ;
      RECT 180.665 553.99 947.27 557.22 ;
      RECT 168.505 560.845 947.27 563.34 ;
      RECT 168.505 560.635 947.27 560.845 ;
      RECT 180.665 554.075 932.41 560.635 ;
      RECT 180.665 554.075 932.41 560.635 ;
      RECT 20.06 345.88 742.415 346.27 ;
      RECT 20.06 344.26 742.735 345.12 ;
      RECT 20.06 343.83 743.295 344.26 ;
      RECT 20.06 343.3 743.295 343.83 ;
      RECT 20.06 342.54 743.295 343.3 ;
      RECT 20.06 342.01 743.295 342.54 ;
      RECT 20.06 337.81 744.155 338.57 ;
      RECT 20.06 335.205 744.155 338.57 ;
      RECT 20.06 336.95 744.155 337.81 ;
      RECT 20.06 336.42 744.155 336.95 ;
      RECT 20.06 335.99 744.155 336.42 ;
      RECT 20.06 335.205 744.155 335.99 ;
      RECT 15 165.125 947.27 231.055 ;
      RECT 20.06 231.055 947.27 322.92 ;
      RECT 20.06 330.67 741.995 338.57 ;
      RECT 20.06 330.67 741.995 337.81 ;
      RECT 20.06 330.175 741.995 337.81 ;
      RECT 57.875 567.275 947.27 567.64 ;
      RECT 57.875 569.495 645.08 571.25 ;
      RECT 57.875 568.395 645.08 569.495 ;
      RECT 57.875 567.64 947.27 568.395 ;
      RECT 57.875 574.955 705.2 579.455 ;
      RECT 57.875 588.395 947.27 601.555 ;
      RECT 922.53 588.395 947.27 605.885 ;
      RECT 394.94 162.925 947.27 163.405 ;
      RECT 396.14 162.445 947.27 231.055 ;
      RECT 396.14 162.445 947.27 231.055 ;
      RECT 396.14 162.445 947.27 231.055 ;
      RECT 396.14 162.445 947.27 231.055 ;
      RECT 396.14 162.445 947.27 231.055 ;
      RECT 396.14 162.445 947.27 231.055 ;
      RECT 15 152.725 947.27 157.16 ;
      RECT 20.06 139.005 947.27 152.725 ;
      RECT 15 571.345 56.53 606.385 ;
      RECT 31.695 571.34 56.53 574.35 ;
      RECT 943.355 489.25 947.27 531.61 ;
      RECT 15 554.355 180.385 560.355 ;
      RECT 15 231.335 19.78 554.355 ;
      RECT 15 561.715 62.39 566.995 ;
      RECT 15 561.125 168.225 564.72 ;
      RECT 31.415 569.775 57.595 571.06 ;
      RECT 56.81 571.06 57.595 606.03 ;
      RECT 15.185 571.06 31.415 571.065 ;
      RECT 15.185 567.92 31.415 571.065 ;
      RECT 15.185 567.92 31.415 571.065 ;
      RECT 15.185 569.775 31.415 571.06 ;
      RECT 15.185 567.92 31.415 569.775 ;
      RECT 345.005 601.835 368.73 603.835 ;
      RECT 694.795 602.735 922.25 605.605 ;
      RECT 15 60.425 19.78 85.395 ;
      RECT 15 139.285 19.78 152.445 ;
      RECT 57.875 605.885 947.27 606.385 ;
      RECT 922.53 603.38 947.27 605.885 ;
      RECT 57.875 604.115 694.515 605.885 ;
      RECT 369.01 602.455 694.515 604.115 ;
      RECT 57.875 601.555 344.725 604.115 ;
      RECT 369.01 599.45 922.53 602.455 ;
      RECT 57.875 580.915 705.2 581.465 ;
      RECT 57.875 582.075 863.625 588.395 ;
      RECT 57.875 581.465 947.27 582.075 ;
      RECT 57.875 580.155 65.01 580.915 ;
      RECT 65.88 580.215 705.2 580.915 ;
      RECT 57.875 579.455 65.005 580.155 ;
      RECT 65.83 577.21 705.2 580.215 ;
      RECT 57.875 571.25 398.2 574.955 ;
      RECT 31.695 567.64 57.875 569.495 ;
      RECT 62.67 565 947.27 568.005 ;
      RECT 26.82 567.275 57.875 567.64 ;
      RECT 168.505 564.1 947.27 565 ;
      RECT 168.505 561.095 932.41 564.1 ;
      RECT 932.41 557.98 947.27 560.985 ;
      RECT 15 560.635 168.505 560.845 ;
      RECT 743.295 343.83 749.985 344.26 ;
      RECT 20.06 342.875 742.26 345.88 ;
      RECT 743.295 343.3 758.47 343.83 ;
      RECT 743.295 342.54 743.69 343.3 ;
      RECT 743.295 342.01 759.775 342.54 ;
      RECT 743.295 341.58 745.175 342.01 ;
      RECT 744.155 340.39 760.705 340.82 ;
      RECT 744.155 339.53 760.73 340.39 ;
      RECT 744.155 339.1 761.11 339.53 ;
      RECT 744.155 338.57 762.025 339.1 ;
      RECT 744.155 336.95 744.59 337.81 ;
      RECT 744.155 336.42 820.17 336.95 ;
      RECT 744.155 335.99 819.655 336.42 ;
      RECT 744.155 335.205 819.135 335.99 ;
      RECT 741.995 334.075 763.34 334.505 ;
      RECT 741.995 333.61 765.89 334.075 ;
      RECT 741.995 333.14 836.59 333.61 ;
      RECT 741.995 332.645 841.11 333.14 ;
      RECT 741.995 332.42 845.635 332.645 ;
      RECT 20.06 332.185 845.635 332.42 ;
      RECT 20.06 331.7 850.255 332.185 ;
      RECT 20.06 331.43 854.74 331.7 ;
      RECT 20.06 330.67 808.87 331.43 ;
      RECT 20.06 330.175 809.565 330.67 ;
      RECT 20.06 329.415 947.27 330.175 ;
      RECT 20.06 324.44 911.145 329.415 ;
      RECT 20.06 322.92 822.76 323.68 ;
      RECT 20.06 323.68 947.27 324.44 ;
      RECT 394.33 162.445 397.335 162.925 ;
      RECT 393.88 161.965 947.27 162.445 ;
      RECT 393.225 161.485 947.27 161.965 ;
      RECT 392.725 161.005 947.27 161.485 ;
      RECT 392.19 160.525 947.27 161.005 ;
      RECT 391.975 160.045 947.27 160.525 ;
      RECT 391.13 159.565 947.27 160.045 ;
      RECT 390.645 159.085 947.27 159.565 ;
      RECT 15 158.88 947.27 159.085 ;
      RECT 392.14 158.12 947.27 158.88 ;
      RECT 391.635 157.64 947.27 158.12 ;
      RECT 390.72 154.635 947.27 157.64 ;
      RECT 43.675 130.555 938.085 131.325 ;
      RECT 938.085 128.115 947.27 128.71 ;
      RECT 15 124.555 740.855 128.115 ;
      RECT 30.17 39.61 239.775 42.615 ;
      RECT 30.17 39.065 235.225 39.61 ;
      RECT 15 38.68 235.225 39.065 ;
      RECT 235.01 32.15 235.225 38.68 ;
      RECT 15 31.67 235.225 32.15 ;
      RECT 15 25.11 23.605 25.14 ;
      RECT 15 15 23.605 25.14 ;
      RECT 20.06 347.91 947.27 380.59 ;
      RECT 20.06 347.54 875.12 380.59 ;
      RECT 20.06 347.54 875.12 380.59 ;
      RECT 20.06 347.54 875.12 380.59 ;
      RECT 20.06 347.54 875.12 380.59 ;
      RECT 20.06 347.54 875.12 380.59 ;
      RECT 20.06 347.54 875.12 380.59 ;
      RECT 20.06 347.54 875.12 380.59 ;
      RECT 20.06 347.54 875.12 347.91 ;
      RECT 20.06 347.17 874.195 380.59 ;
      RECT 20.06 347.17 874.195 380.59 ;
      RECT 20.06 347.17 874.195 380.59 ;
      RECT 20.06 347.17 874.195 380.59 ;
      RECT 20.06 347.17 874.195 380.59 ;
      RECT 20.06 347.17 874.195 380.59 ;
      RECT 20.06 347.17 874.195 380.59 ;
      RECT 20.06 347.17 874.195 347.54 ;
      RECT 20.06 346.74 865.9 347.17 ;
      RECT 20.06 346.27 861.89 346.74 ;
      RECT 20.06 380.59 928.63 381.99 ;
      RECT 20.06 338.57 744.155 339.1 ;
      RECT 20.06 339.1 744.155 339.53 ;
      RECT 20.06 341.58 743.295 342.01 ;
      RECT 20.06 340.82 743.295 341.58 ;
      RECT 20.06 340.39 744.155 340.82 ;
      RECT 20.06 339.53 744.155 340.39 ;
      RECT 20.06 540.145 932.41 540.905 ;
      RECT 20.06 536.67 932.41 540.905 ;
      RECT 20.06 536.67 947.27 540.145 ;
      RECT 0 0 6.31 25.53 ;
      RECT 0 55.65 6.31 78.93 ;
      RECT 0 94.62 6.31 105.265 ;
      RECT 0 120.955 6.31 123.885 ;
      RECT 0 137.995 6.31 150.49 ;
      RECT 0 171.795 6.31 560.335 ;
      RECT 0 574.375 6.31 621.385 ;
      RECT 6.31 0 6.9 25.53 ;
      RECT 6.31 55.65 6.9 78.93 ;
      RECT 6.31 94.62 6.9 105.265 ;
      RECT 6.31 120.955 6.9 123.885 ;
      RECT 6.31 137.995 6.9 150.49 ;
      RECT 6.31 171.795 6.9 560.335 ;
      RECT 6.31 574.375 6.9 621.385 ;
      RECT 6.9 0 14.99 25.53 ;
      RECT 6.9 55.65 14.99 78.93 ;
      RECT 6.9 94.62 14.99 105.265 ;
      RECT 6.9 120.955 14.99 123.885 ;
      RECT 6.9 137.995 14.99 150.49 ;
      RECT 6.9 171.795 14.99 560.335 ;
      RECT 6.9 574.375 14.99 621.385 ;
      RECT 14.99 0 15 25.53 ;
      RECT 14.99 55.65 15 78.93 ;
      RECT 14.99 94.62 15 105.265 ;
      RECT 14.99 120.955 15 123.885 ;
      RECT 14.99 137.995 15 150.49 ;
      RECT 14.99 171.795 15 560.335 ;
      RECT 14.99 574.375 15 621.385 ;
      RECT 947.27 0 947.28 117.155 ;
      RECT 947.27 134.735 947.28 316.3 ;
      RECT 947.27 354.53 947.28 373.97 ;
      RECT 947.27 388.61 947.28 404.05 ;
      RECT 947.27 418.11 947.28 419.64 ;
      RECT 947.27 433.76 947.28 473 ;
      RECT 947.27 588.085 947.28 621.385 ;
      RECT 947.28 0 947.285 117.155 ;
      RECT 947.28 134.735 947.285 316.3 ;
      RECT 947.28 354.53 947.285 373.97 ;
      RECT 947.28 388.61 947.285 404.05 ;
      RECT 947.28 418.11 947.285 419.64 ;
      RECT 947.28 433.76 947.285 473 ;
      RECT 947.28 588.085 947.285 621.385 ;
      RECT 947.285 0 955.37 117.155 ;
      RECT 947.285 134.735 955.37 316.3 ;
      RECT 947.285 354.53 955.37 373.97 ;
      RECT 947.285 388.61 955.37 404.05 ;
      RECT 947.285 418.11 955.37 419.64 ;
      RECT 947.285 433.76 955.37 473 ;
      RECT 947.285 588.085 955.37 621.385 ;
      RECT 955.37 0 962.27 117.155 ;
      RECT 955.37 134.735 962.27 316.3 ;
      RECT 955.37 354.53 962.27 373.97 ;
      RECT 955.37 388.61 962.27 404.05 ;
      RECT 955.37 418.11 962.27 419.64 ;
      RECT 955.37 433.76 962.27 473 ;
      RECT 955.37 588.085 962.27 621.385 ;
      RECT 15 0 947.27 15 ;
      RECT 15 606.385 947.27 621.385 ;
    LAYER met3 ;
      RECT 15 15 947.27 606.385 ;
    LAYER met4 ;
      RECT 15 15 947.27 606.385 ;
  END
END CF_ADC_DSM20

END LIBRARY
